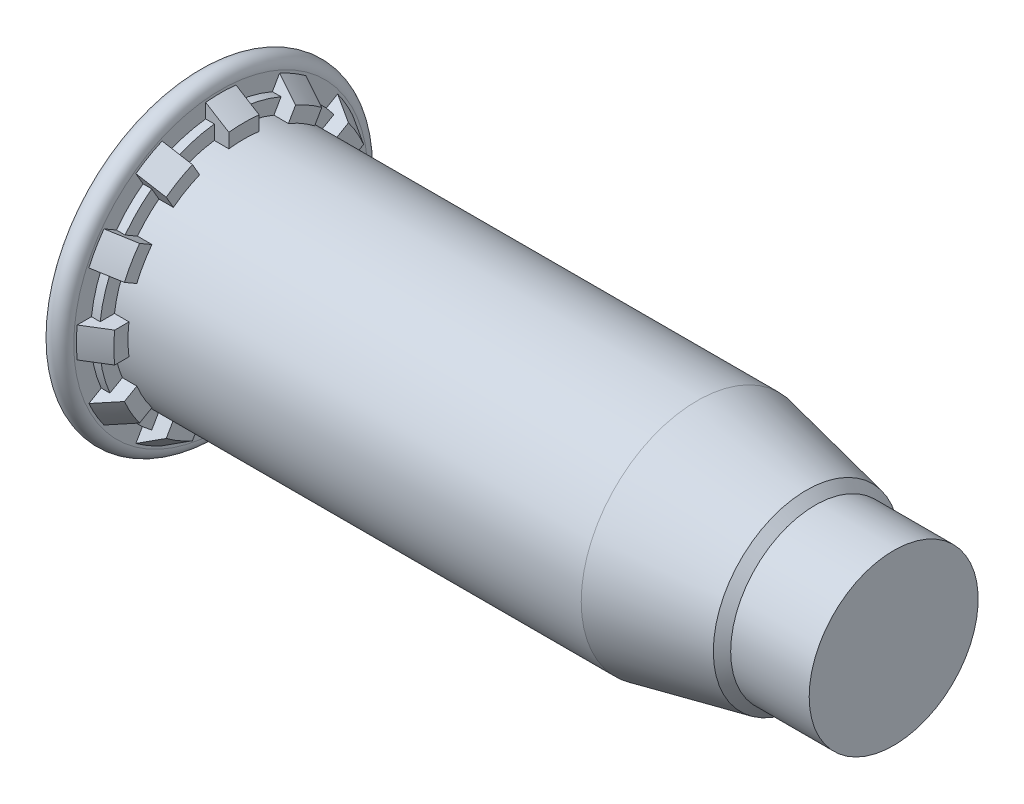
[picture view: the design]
ISO-10303-21;
HEADER;
FILE_DESCRIPTION(('STEP AP214'),'2;1');
FILE_NAME('part.step','',(''),(''),'','','');
FILE_SCHEMA(('AUTOMOTIVE_DESIGN { 1 0 10303 214 1 1 1 1 }'));
ENDSEC;
DATA;
#1=APPLICATION_CONTEXT('core data for automotive mechanical design processes');
#2=APPLICATION_PROTOCOL_DEFINITION('international standard','automotive_design',2000,#1);
#3=PRODUCT_CONTEXT('',#1,'mechanical');
#4=PRODUCT('Part','Part','',(#3));
#5=PRODUCT_RELATED_PRODUCT_CATEGORY('part','',(#4));
#6=PRODUCT_DEFINITION_FORMATION('','',#4);
#7=PRODUCT_DEFINITION_CONTEXT('part definition',#1,'design');
#8=PRODUCT_DEFINITION('design','',#6,#7);
#9=PRODUCT_DEFINITION_SHAPE('','',#8);
#10=(LENGTH_UNIT() NAMED_UNIT(*) SI_UNIT(.MILLI.,.METRE.));
#11=(NAMED_UNIT(*) PLANE_ANGLE_UNIT() SI_UNIT($,.RADIAN.));
#12=(NAMED_UNIT(*) SI_UNIT($,.STERADIAN.) SOLID_ANGLE_UNIT());
#13=UNCERTAINTY_MEASURE_WITH_UNIT(LENGTH_MEASURE(1.E-05),#10,'distance_accuracy_value','');
#14=(GEOMETRIC_REPRESENTATION_CONTEXT(3) GLOBAL_UNCERTAINTY_ASSIGNED_CONTEXT((#13)) GLOBAL_UNIT_ASSIGNED_CONTEXT((#10,
#11,#12)) REPRESENTATION_CONTEXT('',''));
#15=CARTESIAN_POINT('',(0.,0.,0.));
#16=DIRECTION('',(0.,0.,1.));
#17=DIRECTION('',(1.,0.,0.));
#18=AXIS2_PLACEMENT_3D('',#15,#16,#17);
#19=CARTESIAN_POINT('',(0.6,0.,0.));
#20=DIRECTION('',(-1.,0.,0.));
#21=DIRECTION('',(0.,0.,1.));
#22=AXIS2_PLACEMENT_3D('',#19,#20,#21);
#23=CONICAL_SURFACE('',#22,3.735,0.54956001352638);
#24=CARTESIAN_POINT('',(0.6,0.,0.));
#25=DIRECTION('',(-1.,0.,0.));
#26=DIRECTION('',(0.,0.,1.));
#27=AXIS2_PLACEMENT_3D('',#24,#25,#26);
#28=CIRCLE('',#27,3.735);
#29=CARTESIAN_POINT('',(0.6,3.02098991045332,2.19632533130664));
#30=VERTEX_POINT('',#29);
#31=CARTESIAN_POINT('',(0.6,3.41256848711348,1.51809134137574));
#32=VERTEX_POINT('',#31);
#33=EDGE_CURVE('E971',#30,#32,#28,.T.);
#34=ORIENTED_EDGE('',*,*,#33,.F.);
#35=CARTESIAN_POINT('',(1.2002,2.70066079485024,2.01138323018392));
#36=CARTESIAN_POINT('',(1.07508025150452,2.76747981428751,2.04996120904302));
#37=CARTESIAN_POINT('',(0.94994691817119,2.83427974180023,2.08852816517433));
#38=CARTESIAN_POINT('',(0.74980487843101,2.941079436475,2.15018899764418));
#39=CARTESIAN_POINT('',(0.67480487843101,2.98109143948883,2.17328993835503));
#40=CARTESIAN_POINT('',(0.5998,3.0210965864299,2.19638692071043));
#41=B_SPLINE_CURVE_WITH_KNOTS('',3,(#35,#36,#37,#38,#39,#40),.UNSPECIFIED.,.F.,.F.,(4,2,4),(0.,
0.44098970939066,0.705255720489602),.UNSPECIFIED.);
#42=CARTESIAN_POINT('',(1.2,2.70076760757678,2.01144489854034));
#43=VERTEX_POINT('',#42);
#44=EDGE_CURVE('E972',#43,#30,#41,.T.);
#45=ORIENTED_EDGE('',*,*,#44,.F.);
#46=CARTESIAN_POINT('',(1.2,0.,0.));
#47=DIRECTION('',(-1.,0.,0.));
#48=DIRECTION('',(0.,0.,1.));
#49=AXIS2_PLACEMENT_3D('',#46,#47,#48);
#50=CIRCLE('',#49,3.3675);
#51=CARTESIAN_POINT('',(1.2,3.09234618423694,1.33321090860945));
#52=VERTEX_POINT('',#51);
#53=EDGE_CURVE('E1239',#43,#52,#50,.T.);
#54=ORIENTED_EDGE('',*,*,#53,.T.);
#55=CARTESIAN_POINT('',(0.5998,3.41267516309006,1.51815293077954));
#56=CARTESIAN_POINT('',(0.67480487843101,3.37267001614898,1.49505594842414));
#57=CARTESIAN_POINT('',(0.74980487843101,3.33265801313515,1.47195500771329));
#58=CARTESIAN_POINT('',(0.94994691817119,3.22585831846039,1.41029417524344));
#59=CARTESIAN_POINT('',(1.07508025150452,3.15905839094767,1.37172721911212));
#60=CARTESIAN_POINT('',(1.2002,3.0922393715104,1.33314924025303));
#61=B_SPLINE_CURVE_WITH_KNOTS('',3,(#55,#56,#57,#58,#59,#60),.UNSPECIFIED.,.F.,.F.,(4,2,4),(0.,
0.264266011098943,0.705255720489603),.UNSPECIFIED.);
#62=EDGE_CURVE('E853',#32,#52,#61,.T.);
#63=ORIENTED_EDGE('',*,*,#62,.F.);
#64=EDGE_LOOP('',(#34,#45,#54,#63));
#65=FACE_BOUND('',#64,.T.);
#66=ADVANCED_FACE('F39',(#65),#23,.T.);
#67=CARTESIAN_POINT('',(0.5998,2.19638692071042,3.02109658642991));
#68=CARTESIAN_POINT('',(0.674804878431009,2.17328993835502,2.98109143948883));
#69=CARTESIAN_POINT('',(0.74980487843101,2.15018899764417,2.941079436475));
#70=CARTESIAN_POINT('',(0.94994691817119,2.08852816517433,2.83427974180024));
#71=CARTESIAN_POINT('',(1.07508025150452,2.04996120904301,2.76747981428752));
#72=CARTESIAN_POINT('',(1.2002,2.01138323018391,2.70066079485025));
#73=B_SPLINE_CURVE_WITH_KNOTS('',3,(#67,#68,#69,#70,#71,#72),.UNSPECIFIED.,.F.,.F.,(4,2,4),(0.,
0.264266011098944,0.705255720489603),.UNSPECIFIED.);
#74=CARTESIAN_POINT('',(0.6,2.19632533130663,3.02098991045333));
#75=VERTEX_POINT('',#74);
#76=CARTESIAN_POINT('',(1.2,2.01144489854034,2.70076760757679));
#77=VERTEX_POINT('',#76);
#78=EDGE_CURVE('E1281',#75,#77,#73,.T.);
#79=ORIENTED_EDGE('',*,*,#78,.F.);
#80=CARTESIAN_POINT('',(0.6,1.51809134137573,3.41256848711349));
#81=VERTEX_POINT('',#80);
#82=EDGE_CURVE('E501',#81,#75,#28,.T.);
#83=ORIENTED_EDGE('',*,*,#82,.F.);
#84=CARTESIAN_POINT('',(1.2002,1.33314924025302,3.0922393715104));
#85=CARTESIAN_POINT('',(1.07508025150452,1.37172721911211,3.15905839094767));
#86=CARTESIAN_POINT('',(0.94994691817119,1.41029417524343,3.22585831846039));
#87=CARTESIAN_POINT('',(0.749804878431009,1.47195500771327,3.33265801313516));
#88=CARTESIAN_POINT('',(0.674804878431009,1.49505594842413,3.37267001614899));
#89=CARTESIAN_POINT('',(0.5998,1.51815293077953,3.41267516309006));
#90=B_SPLINE_CURVE_WITH_KNOTS('',3,(#84,#85,#86,#87,#88,#89),.UNSPECIFIED.,.F.,.F.,(4,2,4),(0.,
0.440989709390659,0.705255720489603),.UNSPECIFIED.);
#91=CARTESIAN_POINT('',(1.2,1.33321090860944,3.09234618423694));
#92=VERTEX_POINT('',#91);
#93=EDGE_CURVE('E1021',#92,#81,#90,.T.);
#94=ORIENTED_EDGE('',*,*,#93,.F.);
#95=EDGE_CURVE('E1243',#92,#77,#50,.T.);
#96=ORIENTED_EDGE('',*,*,#95,.T.);
#97=EDGE_LOOP('',(#79,#83,#94,#96));
#98=FACE_BOUND('',#97,.T.);
#99=ADVANCED_FACE('F959',(#98),#23,.T.);
#100=CARTESIAN_POINT('',(-0.296527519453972,0.391578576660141,4.26618998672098));
#101=CARTESIAN_POINT('',(-0.286159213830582,0.391578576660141,4.25981269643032));
#102=CARTESIAN_POINT('',(-0.275790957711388,0.391578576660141,4.25343532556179));
#103=CARTESIAN_POINT('',(0.213231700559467,0.391578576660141,3.95263889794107));
#104=CARTESIAN_POINT('',(0.691778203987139,0.391578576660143,3.65804424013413));
#105=CARTESIAN_POINT('',(1.40926693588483,0.391578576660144,3.21561509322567));
#106=CARTESIAN_POINT('',(1.64837471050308,0.391578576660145,3.0680491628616));
#107=CARTESIAN_POINT('',(2.12640919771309,0.391578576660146,2.77262408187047));
#108=CARTESIAN_POINT('',(2.36533591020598,0.391578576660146,2.62476493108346));
#109=CARTESIAN_POINT('',(2.60413661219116,0.391578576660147,2.47670216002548));
#110=B_SPLINE_CURVE_WITH_KNOTS('',3,(#100,#101,#102,#103,#104,#105,#106,#107,#108,#109),
.UNSPECIFIED.,.F.,.F.,(4,2,2,2,4),(0.,0.0365177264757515,1.72238057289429,2.56531223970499,
3.40824436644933),.UNSPECIFIED.);
#111=CARTESIAN_POINT('',(0.6,0.391578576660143,3.71441667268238));
#112=VERTEX_POINT('',#111);
#113=CARTESIAN_POINT('',(1.2,0.391578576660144,3.34465580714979));
#114=VERTEX_POINT('',#113);
#115=EDGE_CURVE('E1020',#112,#114,#110,.T.);
#116=ORIENTED_EDGE('',*,*,#115,.F.);
#117=CARTESIAN_POINT('',(0.6,-0.391578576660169,3.71441667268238));
#118=VERTEX_POINT('',#117);
#119=EDGE_CURVE('E977',#118,#112,#28,.T.);
#120=ORIENTED_EDGE('',*,*,#119,.F.);
#121=CARTESIAN_POINT('',(2.60413661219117,-0.391578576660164,2.47670216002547));
#122=CARTESIAN_POINT('',(2.36533591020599,-0.391578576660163,2.62476493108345));
#123=CARTESIAN_POINT('',(2.12640919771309,-0.391578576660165,2.77262408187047));
#124=CARTESIAN_POINT('',(1.64837471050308,-0.391578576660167,3.0680491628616));
#125=CARTESIAN_POINT('',(1.40926693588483,-0.391578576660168,3.21561509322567));
#126=CARTESIAN_POINT('',(0.691778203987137,-0.391578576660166,3.65804424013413));
#127=CARTESIAN_POINT('',(0.213231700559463,-0.391578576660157,3.95263889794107));
#128=CARTESIAN_POINT('',(-0.275790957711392,-0.391578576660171,4.25343532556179));
#129=CARTESIAN_POINT('',(-0.286159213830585,-0.391578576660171,4.25981269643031));
#130=CARTESIAN_POINT('',(-0.296527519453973,-0.391578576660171,4.26618998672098));
#131=B_SPLINE_CURVE_WITH_KNOTS('',3,(#121,#122,#123,#124,#125,#126,#127,#128,#129,#130),
.UNSPECIFIED.,.F.,.F.,(4,2,2,2,4),(0.,0.842932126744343,1.68586379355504,3.37172663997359,
3.40824436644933),.UNSPECIFIED.);
#132=CARTESIAN_POINT('',(1.2,-0.391578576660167,3.34465580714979));
#133=VERTEX_POINT('',#132);
#134=EDGE_CURVE('E1012',#133,#118,#131,.T.);
#135=ORIENTED_EDGE('',*,*,#134,.F.);
#136=EDGE_CURVE('E1018',#133,#114,#50,.T.);
#137=ORIENTED_EDGE('',*,*,#136,.T.);
#138=EDGE_LOOP('',(#116,#120,#135,#137));
#139=FACE_BOUND('',#138,.T.);
#140=ADVANCED_FACE('F967',(#139),#23,.T.);
#141=CARTESIAN_POINT('',(0.5998,-1.51815293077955,3.41267516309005));
#142=CARTESIAN_POINT('',(0.67480487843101,-1.49505594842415,3.37267001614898));
#143=CARTESIAN_POINT('',(0.74980487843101,-1.4719550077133,3.33265801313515));
#144=CARTESIAN_POINT('',(0.94994691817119,-1.41029417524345,3.22585831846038));
#145=CARTESIAN_POINT('',(1.07508025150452,-1.37172721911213,3.15905839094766));
#146=CARTESIAN_POINT('',(1.2002,-1.33314924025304,3.09223937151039));
#147=B_SPLINE_CURVE_WITH_KNOTS('',3,(#141,#142,#143,#144,#145,#146),.UNSPECIFIED.,.F.,.F.,(4,2,
4),(0.,0.264266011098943,0.705255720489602),.UNSPECIFIED.);
#148=CARTESIAN_POINT('',(0.6,-1.51809134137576,3.41256848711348));
#149=VERTEX_POINT('',#148);
#150=CARTESIAN_POINT('',(1.2,-1.33321090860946,3.09234618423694));
#151=VERTEX_POINT('',#150);
#152=EDGE_CURVE('E1037',#149,#151,#147,.T.);
#153=ORIENTED_EDGE('',*,*,#152,.F.);
#154=CARTESIAN_POINT('',(0.6,-2.19632533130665,3.02098991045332));
#155=VERTEX_POINT('',#154);
#156=EDGE_CURVE('E1004',#155,#149,#28,.T.);
#157=ORIENTED_EDGE('',*,*,#156,.F.);
#158=CARTESIAN_POINT('',(1.2002,-2.01138323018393,2.70066079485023));
#159=CARTESIAN_POINT('',(1.07508025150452,-2.04996120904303,2.7674798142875));
#160=CARTESIAN_POINT('',(0.949946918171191,-2.08852816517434,2.83427974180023));
#161=CARTESIAN_POINT('',(0.74980487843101,-2.15018899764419,2.94107943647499));
#162=CARTESIAN_POINT('',(0.67480487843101,-2.17328993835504,2.98109143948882));
#163=CARTESIAN_POINT('',(0.5998,-2.19638692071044,3.02109658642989));
#164=B_SPLINE_CURVE_WITH_KNOTS('',3,(#158,#159,#160,#161,#162,#163),.UNSPECIFIED.,.F.,.F.,(4,2,
4),(0.,0.44098970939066,0.705255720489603),.UNSPECIFIED.);
#165=CARTESIAN_POINT('',(1.2,-2.01144489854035,2.70076760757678));
#166=VERTEX_POINT('',#165);
#167=EDGE_CURVE('E1087',#166,#155,#164,.T.);
#168=ORIENTED_EDGE('',*,*,#167,.F.);
#169=EDGE_CURVE('E1352',#166,#151,#50,.T.);
#170=ORIENTED_EDGE('',*,*,#169,.T.);
#171=EDGE_LOOP('',(#153,#157,#168,#170));
#172=FACE_BOUND('',#171,.T.);
#173=ADVANCED_FACE('F1489',(#172),#23,.T.);
#174=CARTESIAN_POINT('',(0.5998,-3.02109658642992,2.19638692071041));
#175=CARTESIAN_POINT('',(0.67480487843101,-2.98109143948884,2.17328993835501));
#176=CARTESIAN_POINT('',(0.74980487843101,-2.94107943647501,2.15018899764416));
#177=CARTESIAN_POINT('',(0.94994691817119,-2.83427974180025,2.08852816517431));
#178=CARTESIAN_POINT('',(1.07508025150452,-2.76747981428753,2.049961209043));
#179=CARTESIAN_POINT('',(1.2002,-2.70066079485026,2.0113832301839));
#180=B_SPLINE_CURVE_WITH_KNOTS('',3,(#174,#175,#176,#177,#178,#179),.UNSPECIFIED.,.F.,.F.,(4,2,
4),(0.,0.264266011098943,0.705255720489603),.UNSPECIFIED.);
#181=CARTESIAN_POINT('',(0.6,-3.02098991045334,2.19632533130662));
#182=VERTEX_POINT('',#181);
#183=CARTESIAN_POINT('',(1.2,-2.7007676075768,2.01144489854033));
#184=VERTEX_POINT('',#183);
#185=EDGE_CURVE('E1083',#182,#184,#180,.T.);
#186=ORIENTED_EDGE('',*,*,#185,.F.);
#187=CARTESIAN_POINT('',(0.6,-3.41256848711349,1.51809134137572));
#188=VERTEX_POINT('',#187);
#189=EDGE_CURVE('E999',#188,#182,#28,.T.);
#190=ORIENTED_EDGE('',*,*,#189,.F.);
#191=CARTESIAN_POINT('',(1.2002,-3.09223937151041,1.33314924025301));
#192=CARTESIAN_POINT('',(1.07508025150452,-3.15905839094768,1.3717272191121));
#193=CARTESIAN_POINT('',(0.949946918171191,-3.2258583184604,1.41029417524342));
#194=CARTESIAN_POINT('',(0.74980487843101,-3.33265801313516,1.47195500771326));
#195=CARTESIAN_POINT('',(0.67480487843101,-3.37267001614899,1.49505594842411));
#196=CARTESIAN_POINT('',(0.5998,-3.41267516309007,1.51815293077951));
#197=B_SPLINE_CURVE_WITH_KNOTS('',3,(#191,#192,#193,#194,#195,#196),.UNSPECIFIED.,.F.,.F.,(4,2,
4),(0.,0.44098970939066,0.705255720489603),.UNSPECIFIED.);
#198=CARTESIAN_POINT('',(1.2,-3.09234618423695,1.33321090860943));
#199=VERTEX_POINT('',#198);
#200=EDGE_CURVE('E1123',#199,#188,#197,.T.);
#201=ORIENTED_EDGE('',*,*,#200,.F.);
#202=EDGE_CURVE('E1348',#199,#184,#50,.T.);
#203=ORIENTED_EDGE('',*,*,#202,.T.);
#204=EDGE_LOOP('',(#186,#190,#201,#203));
#205=FACE_BOUND('',#204,.T.);
#206=ADVANCED_FACE('F1456',(#205),#23,.T.);
#207=CARTESIAN_POINT('',(-0.571392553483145,-4.43522558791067,0.391578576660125));
#208=CARTESIAN_POINT('',(-0.33204367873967,-4.28805118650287,0.391578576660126));
#209=CARTESIAN_POINT('',(-0.092717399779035,-4.1408400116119,0.391578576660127));
#210=CARTESIAN_POINT('',(0.385864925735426,-3.84630382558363,0.391578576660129));
#211=CARTESIAN_POINT('',(0.62512097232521,-3.69897881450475,0.39157857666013));
#212=CARTESIAN_POINT('',(1.10353812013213,-3.404174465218,0.391578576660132));
#213=CARTESIAN_POINT('',(1.34269922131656,-3.25669512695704,0.391578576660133));
#214=CARTESIAN_POINT('',(1.82087179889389,-2.96149383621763,0.391578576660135));
#215=CARTESIAN_POINT('',(2.05988327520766,-2.81377188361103,0.391578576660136));
#216=CARTESIAN_POINT('',(2.29879251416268,-2.66588453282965,0.391578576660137));
#217=B_SPLINE_CURVE_WITH_KNOTS('',3,(#207,#208,#209,#210,#211,#212,#213,#214,#215,#216),
.UNSPECIFIED.,.F.,.F.,(4,2,2,2,4),(0.,0.84293162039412,1.68586280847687,2.52879428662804,
3.3717262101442),.UNSPECIFIED.);
#218=CARTESIAN_POINT('',(0.6,-3.71441667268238,0.39157857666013));
#219=VERTEX_POINT('',#218);
#220=CARTESIAN_POINT('',(1.2,-3.34465580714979,0.391578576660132));
#221=VERTEX_POINT('',#220);
#222=EDGE_CURVE('E1116',#219,#221,#217,.T.);
#223=ORIENTED_EDGE('',*,*,#222,.F.);
#224=CARTESIAN_POINT('',(0.6,-3.71441667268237,-0.391578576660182));
#225=VERTEX_POINT('',#224);
#226=EDGE_CURVE('E1000',#225,#219,#28,.T.);
#227=ORIENTED_EDGE('',*,*,#226,.F.);
#228=CARTESIAN_POINT('',(2.29879251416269,-2.66588453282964,-0.391578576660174));
#229=CARTESIAN_POINT('',(2.05988327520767,-2.81377188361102,-0.391578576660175));
#230=CARTESIAN_POINT('',(1.8208717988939,-2.96149383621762,-0.391578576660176));
#231=CARTESIAN_POINT('',(1.34269922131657,-3.25669512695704,-0.391578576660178));
#232=CARTESIAN_POINT('',(1.10353812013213,-3.404174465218,-0.391578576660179));
#233=CARTESIAN_POINT('',(0.625120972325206,-3.69897881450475,-0.391578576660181));
#234=CARTESIAN_POINT('',(0.385864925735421,-3.84630382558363,-0.391578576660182));
#235=CARTESIAN_POINT('',(-0.0927173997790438,-4.1408400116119,-0.391578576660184));
#236=CARTESIAN_POINT('',(-0.33204367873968,-4.28805118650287,-0.391578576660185));
#237=CARTESIAN_POINT('',(-0.571392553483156,-4.43522558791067,-0.391578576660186));
#238=B_SPLINE_CURVE_WITH_KNOTS('',3,(#228,#229,#230,#231,#232,#233,#234,#235,#236,#237),
.UNSPECIFIED.,.F.,.F.,(4,2,2,2,4),(0.,0.842931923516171,1.68586340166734,2.5287945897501,
3.37172621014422),.UNSPECIFIED.);
#239=CARTESIAN_POINT('',(1.2,-3.34465580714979,-0.391578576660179));
#240=VERTEX_POINT('',#239);
#241=EDGE_CURVE('E1137',#240,#225,#238,.T.);
#242=ORIENTED_EDGE('',*,*,#241,.F.);
#243=EDGE_CURVE('E1343',#240,#221,#50,.T.);
#244=ORIENTED_EDGE('',*,*,#243,.T.);
#245=EDGE_LOOP('',(#223,#227,#242,#244));
#246=FACE_BOUND('',#245,.T.);
#247=ADVANCED_FACE('F1454',(#246),#23,.T.);
#248=CARTESIAN_POINT('',(0.5998,-3.41267516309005,-1.51815293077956));
#249=CARTESIAN_POINT('',(0.674804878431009,-3.37267001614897,-1.49505594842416));
#250=CARTESIAN_POINT('',(0.74980487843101,-3.33265801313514,-1.47195500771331));
#251=CARTESIAN_POINT('',(0.94994691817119,-3.22585831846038,-1.41029417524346));
#252=CARTESIAN_POINT('',(1.07508025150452,-3.15905839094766,-1.37172721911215));
#253=CARTESIAN_POINT('',(1.2002,-3.09223937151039,-1.33314924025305));
#254=B_SPLINE_CURVE_WITH_KNOTS('',3,(#248,#249,#250,#251,#252,#253),.UNSPECIFIED.,.F.,.F.,(4,2,
4),(0.,0.264266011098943,0.705255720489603),.UNSPECIFIED.);
#255=CARTESIAN_POINT('',(0.6,-3.41256848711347,-1.51809134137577));
#256=VERTEX_POINT('',#255);
#257=CARTESIAN_POINT('',(1.2,-3.09234618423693,-1.33321090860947));
#258=VERTEX_POINT('',#257);
#259=EDGE_CURVE('E1129',#256,#258,#254,.T.);
#260=ORIENTED_EDGE('',*,*,#259,.F.);
#261=CARTESIAN_POINT('',(0.6,-3.02098991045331,-2.19632533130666));
#262=VERTEX_POINT('',#261);
#263=EDGE_CURVE('E993',#262,#256,#28,.T.);
#264=ORIENTED_EDGE('',*,*,#263,.F.);
#265=CARTESIAN_POINT('',(1.2002,-2.70066079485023,-2.01138323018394));
#266=CARTESIAN_POINT('',(1.07508025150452,-2.7674798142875,-2.04996120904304));
#267=CARTESIAN_POINT('',(0.949946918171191,-2.83427974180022,-2.08852816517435));
#268=CARTESIAN_POINT('',(0.74980487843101,-2.94107943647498,-2.1501889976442));
#269=CARTESIAN_POINT('',(0.67480487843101,-2.98109143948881,-2.17328993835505));
#270=CARTESIAN_POINT('',(0.5998,-3.02109658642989,-2.19638692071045));
#271=B_SPLINE_CURVE_WITH_KNOTS('',3,(#265,#266,#267,#268,#269,#270),.UNSPECIFIED.,.F.,.F.,(4,2,
4),(0.,0.44098970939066,0.705255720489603),.UNSPECIFIED.);
#272=CARTESIAN_POINT('',(1.2,-2.70076760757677,-2.01144489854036));
#273=VERTEX_POINT('',#272);
#274=EDGE_CURVE('E1175',#273,#262,#271,.T.);
#275=ORIENTED_EDGE('',*,*,#274,.F.);
#276=EDGE_CURVE('E1336',#273,#258,#50,.T.);
#277=ORIENTED_EDGE('',*,*,#276,.T.);
#278=EDGE_LOOP('',(#260,#264,#275,#277));
#279=FACE_BOUND('',#278,.T.);
#280=ADVANCED_FACE('F1451',(#279),#23,.T.);
#281=CARTESIAN_POINT('',(0.5998,-2.1963869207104,-3.02109658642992));
#282=CARTESIAN_POINT('',(0.674804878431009,-2.173289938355,-2.98109143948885));
#283=CARTESIAN_POINT('',(0.74980487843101,-2.15018899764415,-2.94107943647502));
#284=CARTESIAN_POINT('',(0.94994691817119,-2.08852816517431,-2.83427974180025));
#285=CARTESIAN_POINT('',(1.07508025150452,-2.04996120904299,-2.76747981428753));
#286=CARTESIAN_POINT('',(1.2002,-2.01138323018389,-2.70066079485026));
#287=B_SPLINE_CURVE_WITH_KNOTS('',3,(#281,#282,#283,#284,#285,#286),.UNSPECIFIED.,.F.,.F.,(4,2,
4),(0.,0.264266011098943,0.705255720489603),.UNSPECIFIED.);
#288=CARTESIAN_POINT('',(0.6,-2.19632533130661,-3.02098991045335));
#289=VERTEX_POINT('',#288);
#290=CARTESIAN_POINT('',(1.2,-2.01144489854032,-2.7007676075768));
#291=VERTEX_POINT('',#290);
#292=EDGE_CURVE('E1166',#289,#291,#287,.T.);
#293=ORIENTED_EDGE('',*,*,#292,.F.);
#294=CARTESIAN_POINT('',(0.6,-1.51809134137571,-3.4125684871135));
#295=VERTEX_POINT('',#294);
#296=EDGE_CURVE('E991',#295,#289,#28,.T.);
#297=ORIENTED_EDGE('',*,*,#296,.F.);
#298=CARTESIAN_POINT('',(1.2002,-1.333149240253,-3.09223937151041));
#299=CARTESIAN_POINT('',(1.07508025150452,-1.37172721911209,-3.15905839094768));
#300=CARTESIAN_POINT('',(0.949946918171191,-1.41029417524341,-3.2258583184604));
#301=CARTESIAN_POINT('',(0.74980487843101,-1.47195500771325,-3.33265801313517));
#302=CARTESIAN_POINT('',(0.67480487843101,-1.4950559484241,-3.372670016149));
#303=CARTESIAN_POINT('',(0.5998,-1.5181529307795,-3.41267516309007));
#304=B_SPLINE_CURVE_WITH_KNOTS('',3,(#298,#299,#300,#301,#302,#303),.UNSPECIFIED.,.F.,.F.,(4,2,
4),(0.,0.44098970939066,0.705255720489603),.UNSPECIFIED.);
#305=CARTESIAN_POINT('',(1.2,-1.33321090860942,-3.09234618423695));
#306=VERTEX_POINT('',#305);
#307=EDGE_CURVE('E1183',#306,#295,#304,.T.);
#308=ORIENTED_EDGE('',*,*,#307,.F.);
#309=EDGE_CURVE('E1338',#306,#291,#50,.T.);
#310=ORIENTED_EDGE('',*,*,#309,.T.);
#311=EDGE_LOOP('',(#293,#297,#308,#310));
#312=FACE_BOUND('',#311,.T.);
#313=ADVANCED_FACE('F1435',(#312),#23,.T.);
#314=CARTESIAN_POINT('',(-0.571392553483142,-0.391578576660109,-4.43522558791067));
#315=CARTESIAN_POINT('',(-0.332043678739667,-0.391578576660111,-4.28805118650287));
#316=CARTESIAN_POINT('',(-0.0927173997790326,-0.391578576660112,-4.1408400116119));
#317=CARTESIAN_POINT('',(0.385864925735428,-0.391578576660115,-3.84630382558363));
#318=CARTESIAN_POINT('',(0.625120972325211,-0.391578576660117,-3.69897881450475));
#319=CARTESIAN_POINT('',(1.10353812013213,-0.39157857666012,-3.404174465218));
#320=CARTESIAN_POINT('',(1.34269922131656,-0.391578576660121,-3.25669512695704));
#321=CARTESIAN_POINT('',(1.82087179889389,-0.391578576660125,-2.96149383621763));
#322=CARTESIAN_POINT('',(2.05988327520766,-0.391578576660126,-2.81377188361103));
#323=CARTESIAN_POINT('',(2.29879251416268,-0.391578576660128,-2.66588453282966));
#324=B_SPLINE_CURVE_WITH_KNOTS('',3,(#314,#315,#316,#317,#318,#319,#320,#321,#322,#323),
.UNSPECIFIED.,.F.,.F.,(4,2,2,2,4),(0.,0.842931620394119,1.68586280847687,2.52879428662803,
3.3717262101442),.UNSPECIFIED.);
#325=CARTESIAN_POINT('',(0.6,-0.391578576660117,-3.71441667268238));
#326=VERTEX_POINT('',#325);
#327=CARTESIAN_POINT('',(1.2,-0.391578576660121,-3.34465580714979));
#328=VERTEX_POINT('',#327);
#329=EDGE_CURVE('E1179',#326,#328,#324,.T.);
#330=ORIENTED_EDGE('',*,*,#329,.F.);
#331=CARTESIAN_POINT('',(0.6,0.391578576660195,-3.71441667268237));
#332=VERTEX_POINT('',#331);
#333=EDGE_CURVE('E986',#332,#326,#28,.T.);
#334=ORIENTED_EDGE('',*,*,#333,.F.);
#335=CARTESIAN_POINT('',(2.29879251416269,0.391578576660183,-2.66588453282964));
#336=CARTESIAN_POINT('',(2.05988327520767,0.391578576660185,-2.81377188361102));
#337=CARTESIAN_POINT('',(1.8208717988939,0.391578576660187,-2.96149383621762));
#338=CARTESIAN_POINT('',(1.34269922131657,0.39157857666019,-3.25669512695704));
#339=CARTESIAN_POINT('',(1.10353812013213,0.391578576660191,-3.404174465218));
#340=CARTESIAN_POINT('',(0.625120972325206,0.391578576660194,-3.69897881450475));
#341=CARTESIAN_POINT('',(0.38586492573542,0.391578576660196,-3.84630382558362));
#342=CARTESIAN_POINT('',(-0.0927173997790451,0.391578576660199,-4.1408400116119));
#343=CARTESIAN_POINT('',(-0.332043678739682,0.3915785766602,-4.28805118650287));
#344=CARTESIAN_POINT('',(-0.571392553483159,0.391578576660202,-4.43522558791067));
#345=B_SPLINE_CURVE_WITH_KNOTS('',3,(#335,#336,#337,#338,#339,#340,#341,#342,#343,#344),
.UNSPECIFIED.,.F.,.F.,(4,2,2,2,4),(0.,0.842931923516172,1.68586340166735,2.5287945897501,
3.37172621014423),.UNSPECIFIED.);
#346=CARTESIAN_POINT('',(1.2,0.391578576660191,-3.34465580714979));
#347=VERTEX_POINT('',#346);
#348=EDGE_CURVE('E1220',#347,#332,#345,.T.);
#349=ORIENTED_EDGE('',*,*,#348,.F.);
#350=EDGE_CURVE('E1244',#347,#328,#50,.T.);
#351=ORIENTED_EDGE('',*,*,#350,.T.);
#352=EDGE_LOOP('',(#330,#334,#349,#351));
#353=FACE_BOUND('',#352,.T.);
#354=ADVANCED_FACE('F1441',(#353),#23,.T.);
#355=CARTESIAN_POINT('',(0.5998,1.51815293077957,-3.41267516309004));
#356=CARTESIAN_POINT('',(0.67480487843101,1.49505594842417,-3.37267001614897));
#357=CARTESIAN_POINT('',(0.74980487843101,1.47195500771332,-3.33265801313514));
#358=CARTESIAN_POINT('',(0.94994691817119,1.41029417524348,-3.22585831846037));
#359=CARTESIAN_POINT('',(1.07508025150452,1.37172721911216,-3.15905839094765));
#360=CARTESIAN_POINT('',(1.2002,1.33314924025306,-3.09223937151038));
#361=B_SPLINE_CURVE_WITH_KNOTS('',3,(#355,#356,#357,#358,#359,#360),.UNSPECIFIED.,.F.,.F.,(4,2,
4),(0.,0.264266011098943,0.705255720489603),.UNSPECIFIED.);
#362=CARTESIAN_POINT('',(0.6,1.51809134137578,-3.41256848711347));
#363=VERTEX_POINT('',#362);
#364=CARTESIAN_POINT('',(1.2,1.33321090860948,-3.09234618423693));
#365=VERTEX_POINT('',#364);
#366=EDGE_CURVE('E1215',#363,#365,#361,.T.);
#367=ORIENTED_EDGE('',*,*,#366,.F.);
#368=CARTESIAN_POINT('',(0.6,2.19632533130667,-3.0209899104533));
#369=VERTEX_POINT('',#368);
#370=EDGE_CURVE('E979',#369,#363,#28,.T.);
#371=ORIENTED_EDGE('',*,*,#370,.F.);
#372=CARTESIAN_POINT('',(1.2002,2.01138323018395,-2.70066079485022));
#373=CARTESIAN_POINT('',(1.07508025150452,2.04996120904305,-2.76747981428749));
#374=CARTESIAN_POINT('',(0.94994691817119,2.08852816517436,-2.83427974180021));
#375=CARTESIAN_POINT('',(0.74980487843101,2.15018899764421,-2.94107943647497));
#376=CARTESIAN_POINT('',(0.67480487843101,2.17328993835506,-2.9810914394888));
#377=CARTESIAN_POINT('',(0.5998,2.19638692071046,-3.02109658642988));
#378=B_SPLINE_CURVE_WITH_KNOTS('',3,(#372,#373,#374,#375,#376,#377),.UNSPECIFIED.,.F.,.F.,(4,2,
4),(0.,0.440989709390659,0.705255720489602),.UNSPECIFIED.);
#379=CARTESIAN_POINT('',(1.2,2.01144489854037,-2.70076760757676));
#380=VERTEX_POINT('',#379);
#381=EDGE_CURVE('E665',#380,#369,#378,.T.);
#382=ORIENTED_EDGE('',*,*,#381,.F.);
#383=EDGE_CURVE('E1238',#380,#365,#50,.T.);
#384=ORIENTED_EDGE('',*,*,#383,.T.);
#385=EDGE_LOOP('',(#367,#371,#382,#384));
#386=FACE_BOUND('',#385,.T.);
#387=ADVANCED_FACE('F1443',(#386),#23,.T.);
#388=CARTESIAN_POINT('',(0.6,3.71441667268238,0.391578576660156));
#389=VERTEX_POINT('',#388);
#390=CARTESIAN_POINT('',(0.6,3.71441667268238,-0.391578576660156));
#391=VERTEX_POINT('',#390);
#392=EDGE_CURVE('E975',#389,#391,#28,.T.);
#393=ORIENTED_EDGE('',*,*,#392,.F.);
#394=CARTESIAN_POINT('',(2.60413661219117,2.47670216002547,0.391578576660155));
#395=CARTESIAN_POINT('',(2.36533591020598,2.62476493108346,0.391578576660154));
#396=CARTESIAN_POINT('',(2.12640919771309,2.77262408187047,0.391578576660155));
#397=CARTESIAN_POINT('',(1.64837471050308,3.0680491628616,0.391578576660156));
#398=CARTESIAN_POINT('',(1.40926693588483,3.21561509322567,0.391578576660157));
#399=CARTESIAN_POINT('',(0.691778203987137,3.65804424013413,0.391578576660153));
#400=CARTESIAN_POINT('',(0.213231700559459,3.95263889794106,0.391578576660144));
#401=CARTESIAN_POINT('',(-0.275790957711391,4.25343532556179,0.391578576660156));
#402=CARTESIAN_POINT('',(-0.286159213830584,4.25981269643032,0.391578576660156));
#403=CARTESIAN_POINT('',(-0.296527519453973,4.26618998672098,0.391578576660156));
#404=B_SPLINE_CURVE_WITH_KNOTS('',3,(#394,#395,#396,#397,#398,#399,#400,#401,#402,#403),
.UNSPECIFIED.,.F.,.F.,(4,2,2,2,4),(0.,0.842932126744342,1.68586379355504,3.37172663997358,
3.40824436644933),.UNSPECIFIED.);
#405=CARTESIAN_POINT('',(1.2,3.34465580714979,0.391578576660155));
#406=VERTEX_POINT('',#405);
#407=EDGE_CURVE('E863',#406,#389,#404,.T.);
#408=ORIENTED_EDGE('',*,*,#407,.F.);
#409=CARTESIAN_POINT('',(1.2,3.34465580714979,-0.391578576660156));
#410=VERTEX_POINT('',#409);
#411=EDGE_CURVE('E1242',#406,#410,#50,.T.);
#412=ORIENTED_EDGE('',*,*,#411,.T.);
#413=CARTESIAN_POINT('',(-0.296527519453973,4.26618998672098,-0.391578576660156));
#414=CARTESIAN_POINT('',(-0.286159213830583,4.25981269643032,-0.391578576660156));
#415=CARTESIAN_POINT('',(-0.27579095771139,4.25343532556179,-0.391578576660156));
#416=CARTESIAN_POINT('',(0.213231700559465,3.95263889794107,-0.391578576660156));
#417=CARTESIAN_POINT('',(0.691778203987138,3.65804424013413,-0.391578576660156));
#418=CARTESIAN_POINT('',(1.40926693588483,3.21561509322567,-0.391578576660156));
#419=CARTESIAN_POINT('',(1.64837471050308,3.0680491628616,-0.391578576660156));
#420=CARTESIAN_POINT('',(2.12640919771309,2.77262408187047,-0.391578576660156));
#421=CARTESIAN_POINT('',(2.36533591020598,2.62476493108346,-0.391578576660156));
#422=CARTESIAN_POINT('',(2.60413661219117,2.47670216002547,-0.391578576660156));
#423=B_SPLINE_CURVE_WITH_KNOTS('',3,(#413,#414,#415,#416,#417,#418,#419,#420,#421,#422),
.UNSPECIFIED.,.F.,.F.,(4,2,2,2,4),(0.,0.0365177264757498,1.72238057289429,2.56531223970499,
3.40824436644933),.UNSPECIFIED.);
#424=EDGE_CURVE('E907',#391,#410,#423,.T.);
#425=ORIENTED_EDGE('',*,*,#424,.F.);
#426=EDGE_LOOP('',(#393,#408,#412,#425));
#427=FACE_BOUND('',#426,.T.);
#428=ADVANCED_FACE('F951',(#427),#23,.T.);
#429=CARTESIAN_POINT('',(1.2,3.3675,0.));
#430=DIRECTION('',(1.,0.,0.));
#431=DIRECTION('',(0.,0.,-1.));
#432=AXIS2_PLACEMENT_3D('',#429,#430,#431);
#433=PLANE('',#432);
#434=DIRECTION('',(0.,-0.499999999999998,-0.86602540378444));
#435=VECTOR('',#434,1.);
#436=CARTESIAN_POINT('',(1.2,1.82628428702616,2.38006002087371));
#437=LINE('',#436,#435);
#438=CARTESIAN_POINT('',(1.2,1.82628428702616,2.38006002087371));
#439=VERTEX_POINT('',#438);
#440=EDGE_CURVE('E652',#77,#439,#437,.T.);
#441=ORIENTED_EDGE('',*,*,#440,.F.);
#442=ORIENTED_EDGE('',*,*,#95,.F.);
#443=DIRECTION('',(0.,0.499999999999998,0.86602540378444));
#444=VECTOR('',#443,1.);
#445=CARTESIAN_POINT('',(1.2,1.14805029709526,2.77163859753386));
#446=LINE('',#445,#444);
#447=CARTESIAN_POINT('',(1.2,1.14805029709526,2.77163859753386));
#448=VERTEX_POINT('',#447);
#449=EDGE_CURVE('E673',#448,#92,#446,.T.);
#450=ORIENTED_EDGE('',*,*,#449,.F.);
#451=CARTESIAN_POINT('',(1.2,0.,0.));
#452=DIRECTION('',(-1.,0.,0.));
#453=DIRECTION('',(0.,0.,1.));
#454=AXIS2_PLACEMENT_3D('',#451,#452,#453);
#455=CIRCLE('',#454,3.);
#456=EDGE_CURVE('E1260',#448,#439,#455,.T.);
#457=ORIENTED_EDGE('',*,*,#456,.T.);
#458=EDGE_LOOP('',(#441,#442,#450,#457));
#459=FACE_BOUND('',#458,.T.);
#460=ADVANCED_FACE('F944',(#459),#433,.T.);
#461=DIRECTION('',(0.,0.,-1.));
#462=VECTOR('',#461,1.);
#463=CARTESIAN_POINT('',(1.2,0.391578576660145,2.97433458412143));
#464=LINE('',#463,#462);
#465=CARTESIAN_POINT('',(1.2,0.391578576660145,2.97433458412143));
#466=VERTEX_POINT('',#465);
#467=EDGE_CURVE('E669',#114,#466,#464,.T.);
#468=ORIENTED_EDGE('',*,*,#467,.F.);
#469=ORIENTED_EDGE('',*,*,#136,.F.);
#470=DIRECTION('',(0.,0.,1.));
#471=VECTOR('',#470,1.);
#472=CARTESIAN_POINT('',(1.2,-0.391578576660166,2.97433458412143));
#473=LINE('',#472,#471);
#474=CARTESIAN_POINT('',(1.2,-0.391578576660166,2.97433458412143));
#475=VERTEX_POINT('',#474);
#476=EDGE_CURVE('E687',#475,#133,#473,.T.);
#477=ORIENTED_EDGE('',*,*,#476,.F.);
#478=EDGE_CURVE('E1389',#475,#466,#455,.T.);
#479=ORIENTED_EDGE('',*,*,#478,.T.);
#480=EDGE_LOOP('',(#468,#469,#477,#479));
#481=FACE_BOUND('',#480,.T.);
#482=ADVANCED_FACE('F952',(#481),#433,.T.);
#483=DIRECTION('',(0.,0.500000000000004,-0.866025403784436));
#484=VECTOR('',#483,1.);
#485=CARTESIAN_POINT('',(1.2,-1.14805029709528,2.77163859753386));
#486=LINE('',#485,#484);
#487=CARTESIAN_POINT('',(1.2,-1.14805029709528,2.77163859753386));
#488=VERTEX_POINT('',#487);
#489=EDGE_CURVE('E685',#151,#488,#486,.T.);
#490=ORIENTED_EDGE('',*,*,#489,.F.);
#491=ORIENTED_EDGE('',*,*,#169,.F.);
#492=DIRECTION('',(0.,-0.500000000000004,0.866025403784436));
#493=VECTOR('',#492,1.);
#494=CARTESIAN_POINT('',(1.2,-1.82628428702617,2.3800600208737));
#495=LINE('',#494,#493);
#496=CARTESIAN_POINT('',(1.2,-1.82628428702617,2.3800600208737));
#497=VERTEX_POINT('',#496);
#498=EDGE_CURVE('E710',#497,#166,#495,.T.);
#499=ORIENTED_EDGE('',*,*,#498,.F.);
#500=EDGE_CURVE('E1395',#497,#488,#455,.T.);
#501=ORIENTED_EDGE('',*,*,#500,.T.);
#502=EDGE_LOOP('',(#490,#491,#499,#501));
#503=FACE_BOUND('',#502,.T.);
#504=ADVANCED_FACE('F1486',(#503),#433,.T.);
#505=DIRECTION('',(0.,0.866025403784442,-0.499999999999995));
#506=VECTOR('',#505,1.);
#507=CARTESIAN_POINT('',(1.2,-2.38006002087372,1.82628428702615));
#508=LINE('',#507,#506);
#509=CARTESIAN_POINT('',(1.2,-2.38006002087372,1.82628428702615));
#510=VERTEX_POINT('',#509);
#511=EDGE_CURVE('E701',#184,#510,#508,.T.);
#512=ORIENTED_EDGE('',*,*,#511,.F.);
#513=ORIENTED_EDGE('',*,*,#202,.F.);
#514=DIRECTION('',(0.,-0.866025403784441,0.499999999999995));
#515=VECTOR('',#514,1.);
#516=CARTESIAN_POINT('',(1.2,-2.77163859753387,1.14805029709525));
#517=LINE('',#516,#515);
#518=CARTESIAN_POINT('',(1.2,-2.77163859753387,1.14805029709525));
#519=VERTEX_POINT('',#518);
#520=EDGE_CURVE('E721',#519,#199,#517,.T.);
#521=ORIENTED_EDGE('',*,*,#520,.F.);
#522=EDGE_CURVE('E1398',#519,#510,#455,.T.);
#523=ORIENTED_EDGE('',*,*,#522,.T.);
#524=EDGE_LOOP('',(#512,#513,#521,#523));
#525=FACE_BOUND('',#524,.T.);
#526=ADVANCED_FACE('F1478',(#525),#433,.T.);
#527=DIRECTION('',(0.,1.,0.));
#528=VECTOR('',#527,1.);
#529=CARTESIAN_POINT('',(1.2,-2.97433458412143,0.391578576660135));
#530=LINE('',#529,#528);
#531=CARTESIAN_POINT('',(1.2,-2.97433458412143,0.391578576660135));
#532=VERTEX_POINT('',#531);
#533=EDGE_CURVE('E717',#221,#532,#530,.T.);
#534=ORIENTED_EDGE('',*,*,#533,.F.);
#535=ORIENTED_EDGE('',*,*,#243,.F.);
#536=DIRECTION('',(0.,-1.,0.));
#537=VECTOR('',#536,1.);
#538=CARTESIAN_POINT('',(1.2,-2.97433458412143,-0.391578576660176));
#539=LINE('',#538,#537);
#540=CARTESIAN_POINT('',(1.2,-2.97433458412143,-0.391578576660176));
#541=VERTEX_POINT('',#540);
#542=EDGE_CURVE('E742',#541,#240,#539,.T.);
#543=ORIENTED_EDGE('',*,*,#542,.F.);
#544=EDGE_CURVE('E1405',#541,#532,#455,.T.);
#545=ORIENTED_EDGE('',*,*,#544,.T.);
#546=EDGE_LOOP('',(#534,#535,#543,#545));
#547=FACE_BOUND('',#546,.T.);
#548=ADVANCED_FACE('F1470',(#547),#433,.T.);
#549=DIRECTION('',(0.,0.866025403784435,0.500000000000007));
#550=VECTOR('',#549,1.);
#551=CARTESIAN_POINT('',(1.2,-2.77163859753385,-1.14805029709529));
#552=LINE('',#551,#550);
#553=CARTESIAN_POINT('',(1.2,-2.77163859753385,-1.14805029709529));
#554=VERTEX_POINT('',#553);
#555=EDGE_CURVE('E735',#258,#554,#552,.T.);
#556=ORIENTED_EDGE('',*,*,#555,.F.);
#557=ORIENTED_EDGE('',*,*,#276,.F.);
#558=DIRECTION('',(0.,-0.866025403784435,-0.500000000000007));
#559=VECTOR('',#558,1.);
#560=CARTESIAN_POINT('',(1.2,-2.38006002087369,-1.82628428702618));
#561=LINE('',#560,#559);
#562=CARTESIAN_POINT('',(1.2,-2.38006002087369,-1.82628428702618));
#563=VERTEX_POINT('',#562);
#564=EDGE_CURVE('E758',#563,#273,#561,.T.);
#565=ORIENTED_EDGE('',*,*,#564,.F.);
#566=EDGE_CURVE('E1408',#563,#554,#455,.T.);
#567=ORIENTED_EDGE('',*,*,#566,.T.);
#568=EDGE_LOOP('',(#556,#557,#565,#567));
#569=FACE_BOUND('',#568,.T.);
#570=ADVANCED_FACE('F1586',(#569),#433,.T.);
#571=DIRECTION('',(0.,0.499999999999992,0.866025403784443));
#572=VECTOR('',#571,1.);
#573=CARTESIAN_POINT('',(1.2,-1.82628428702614,-2.38006002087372));
#574=LINE('',#573,#572);
#575=CARTESIAN_POINT('',(1.2,-1.82628428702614,-2.38006002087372));
#576=VERTEX_POINT('',#575);
#577=EDGE_CURVE('E755',#291,#576,#574,.T.);
#578=ORIENTED_EDGE('',*,*,#577,.F.);
#579=ORIENTED_EDGE('',*,*,#309,.F.);
#580=DIRECTION('',(0.,-0.499999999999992,-0.866025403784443));
#581=VECTOR('',#580,1.);
#582=CARTESIAN_POINT('',(1.2,-1.14805029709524,-2.77163859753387));
#583=LINE('',#582,#581);
#584=CARTESIAN_POINT('',(1.2,-1.14805029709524,-2.77163859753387));
#585=VERTEX_POINT('',#584);
#586=EDGE_CURVE('E773',#585,#306,#583,.T.);
#587=ORIENTED_EDGE('',*,*,#586,.F.);
#588=EDGE_CURVE('E1412',#585,#576,#455,.T.);
#589=ORIENTED_EDGE('',*,*,#588,.T.);
#590=EDGE_LOOP('',(#578,#579,#587,#589));
#591=FACE_BOUND('',#590,.T.);
#592=ADVANCED_FACE('F1421',(#591),#433,.T.);
#593=DIRECTION('',(0.,0.,1.));
#594=VECTOR('',#593,1.);
#595=CARTESIAN_POINT('',(1.2,-0.391578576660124,-2.97433458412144));
#596=LINE('',#595,#594);
#597=CARTESIAN_POINT('',(1.2,-0.391578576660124,-2.97433458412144));
#598=VERTEX_POINT('',#597);
#599=EDGE_CURVE('E768',#328,#598,#596,.T.);
#600=ORIENTED_EDGE('',*,*,#599,.F.);
#601=ORIENTED_EDGE('',*,*,#350,.F.);
#602=DIRECTION('',(0.,0.,-1.));
#603=VECTOR('',#602,1.);
#604=CARTESIAN_POINT('',(1.2,0.391578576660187,-2.97433458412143));
#605=LINE('',#604,#603);
#606=CARTESIAN_POINT('',(1.2,0.391578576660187,-2.97433458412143));
#607=VERTEX_POINT('',#606);
#608=EDGE_CURVE('E795',#607,#347,#605,.T.);
#609=ORIENTED_EDGE('',*,*,#608,.F.);
#610=EDGE_CURVE('E1255',#607,#598,#455,.T.);
#611=ORIENTED_EDGE('',*,*,#610,.T.);
#612=EDGE_LOOP('',(#600,#601,#609,#611));
#613=FACE_BOUND('',#612,.T.);
#614=ADVANCED_FACE('F1331',(#613),#433,.T.);
#615=DIRECTION('',(0.,-0.50000000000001,0.866025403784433));
#616=VECTOR('',#615,1.);
#617=CARTESIAN_POINT('',(1.2,1.1480502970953,-2.77163859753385));
#618=LINE('',#617,#616);
#619=CARTESIAN_POINT('',(1.2,1.1480502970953,-2.77163859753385));
#620=VERTEX_POINT('',#619);
#621=EDGE_CURVE('E787',#365,#620,#618,.T.);
#622=ORIENTED_EDGE('',*,*,#621,.F.);
#623=ORIENTED_EDGE('',*,*,#383,.F.);
#624=DIRECTION('',(0.,0.50000000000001,-0.866025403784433));
#625=VECTOR('',#624,1.);
#626=CARTESIAN_POINT('',(1.2,1.82628428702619,-2.38006002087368));
#627=LINE('',#626,#625);
#628=CARTESIAN_POINT('',(1.2,1.82628428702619,-2.38006002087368));
#629=VERTEX_POINT('',#628);
#630=EDGE_CURVE('E647',#629,#380,#627,.T.);
#631=ORIENTED_EDGE('',*,*,#630,.F.);
#632=EDGE_CURVE('E1251',#629,#620,#455,.T.);
#633=ORIENTED_EDGE('',*,*,#632,.T.);
#634=EDGE_LOOP('',(#622,#623,#631,#633));
#635=FACE_BOUND('',#634,.T.);
#636=ADVANCED_FACE('F1608',(#635),#433,.T.);
#637=DIRECTION('',(0.,-0.866025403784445,0.499999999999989));
#638=VECTOR('',#637,1.);
#639=CARTESIAN_POINT('',(1.2,2.38006002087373,-1.82628428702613));
#640=LINE('',#639,#638);
#641=CARTESIAN_POINT('',(1.2,2.70076760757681,-2.01144489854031));
#642=VERTEX_POINT('',#641);
#643=CARTESIAN_POINT('',(1.2,2.38006002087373,-1.82628428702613));
#644=VERTEX_POINT('',#643);
#645=EDGE_CURVE('E802',#642,#644,#640,.T.);
#646=ORIENTED_EDGE('',*,*,#645,.F.);
#647=CARTESIAN_POINT('',(1.2,3.09234618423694,-1.33321090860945));
#648=VERTEX_POINT('',#647);
#649=EDGE_CURVE('E978',#648,#642,#50,.T.);
#650=ORIENTED_EDGE('',*,*,#649,.F.);
#651=DIRECTION('',(0.,0.866025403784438,-0.500000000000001));
#652=VECTOR('',#651,1.);
#653=CARTESIAN_POINT('',(1.2,2.77163859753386,-1.14805029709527));
#654=LINE('',#653,#652);
#655=CARTESIAN_POINT('',(1.2,2.77163859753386,-1.14805029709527));
#656=VERTEX_POINT('',#655);
#657=EDGE_CURVE('E883',#656,#648,#654,.T.);
#658=ORIENTED_EDGE('',*,*,#657,.F.);
#659=EDGE_CURVE('E1240',#656,#644,#455,.T.);
#660=ORIENTED_EDGE('',*,*,#659,.T.);
#661=EDGE_LOOP('',(#646,#650,#658,#660));
#662=FACE_BOUND('',#661,.T.);
#663=ADVANCED_FACE('F960',(#662),#433,.T.);
#664=DIRECTION('',(0.,0.866025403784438,0.500000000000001));
#665=VECTOR('',#664,1.);
#666=CARTESIAN_POINT('',(1.2,2.3800600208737,1.82628428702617));
#667=LINE('',#666,#665);
#668=CARTESIAN_POINT('',(1.2,2.3800600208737,1.82628428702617));
#669=VERTEX_POINT('',#668);
#670=EDGE_CURVE('E659',#669,#43,#667,.T.);
#671=ORIENTED_EDGE('',*,*,#670,.F.);
#672=CARTESIAN_POINT('',(1.2,2.77163859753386,1.14805029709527));
#673=VERTEX_POINT('',#672);
#674=EDGE_CURVE('E1252',#669,#673,#455,.T.);
#675=ORIENTED_EDGE('',*,*,#674,.T.);
#676=DIRECTION('',(0.,-0.866025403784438,-0.500000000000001));
#677=VECTOR('',#676,1.);
#678=CARTESIAN_POINT('',(1.2,2.77163859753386,1.14805029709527));
#679=LINE('',#678,#677);
#680=EDGE_CURVE('E1279',#52,#673,#679,.T.);
#681=ORIENTED_EDGE('',*,*,#680,.F.);
#682=ORIENTED_EDGE('',*,*,#53,.F.);
#683=EDGE_LOOP('',(#671,#675,#681,#682));
#684=FACE_BOUND('',#683,.T.);
#685=ADVANCED_FACE('F948',(#684),#433,.T.);
#686=CARTESIAN_POINT('',(0.,0.,0.));
#687=DIRECTION('',(-1.,0.,0.));
#688=DIRECTION('',(0.,0.,1.));
#689=AXIS2_PLACEMENT_3D('',#686,#687,#688);
#690=PLANE('',#689);
#691=CARTESIAN_POINT('',(0.,0.,0.));
#692=DIRECTION('',(-1.,0.,0.));
#693=DIRECTION('',(0.,0.,1.));
#694=AXIS2_PLACEMENT_3D('',#691,#692,#693);
#695=CIRCLE('',#694,3.79746);
#696=CARTESIAN_POINT('',(0.,0.,3.79746));
#697=VERTEX_POINT('',#696);
#698=EDGE_CURVE('E1291',#697,#697,#695,.T.);
#699=ORIENTED_EDGE('',*,*,#698,.T.);
#700=EDGE_LOOP('',(#699));
#701=FACE_BOUND('',#700,.T.);
#702=ADVANCED_FACE('F41',(#701),#690,.T.);
#703=CARTESIAN_POINT('',(0.,0.,0.));
#704=DIRECTION('',(-1.,0.,0.));
#705=DIRECTION('',(0.,0.,1.));
#706=AXIS2_PLACEMENT_3D('',#703,#704,#705);
#707=CYLINDRICAL_SURFACE('',#706,3.79746);
#708=CARTESIAN_POINT('',(0.00508000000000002,0.,0.));
#709=DIRECTION('',(-1.,0.,0.));
#710=DIRECTION('',(0.,0.,1.));
#711=AXIS2_PLACEMENT_3D('',#708,#709,#710);
#712=CIRCLE('',#711,3.79746);
#713=CARTESIAN_POINT('',(0.00508000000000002,0.,3.79746));
#714=VERTEX_POINT('',#713);
#715=EDGE_CURVE('E1298',#714,#714,#712,.T.);
#716=ORIENTED_EDGE('',*,*,#715,.T.);
#717=EDGE_LOOP('',(#716));
#718=FACE_BOUND('',#717,.T.);
#719=ORIENTED_EDGE('',*,*,#698,.F.);
#720=EDGE_LOOP('',(#719));
#721=FACE_BOUND('',#720,.T.);
#722=ADVANCED_FACE('F2217',(#718,#721),#707,.T.);
#723=CARTESIAN_POINT('',(0.00508,3.80254,0.));
#724=DIRECTION('',(1.,0.,0.));
#725=DIRECTION('',(0.,0.,-1.));
#726=AXIS2_PLACEMENT_3D('',#723,#724,#725);
#727=PLANE('',#726);
#728=ORIENTED_EDGE('',*,*,#715,.F.);
#729=EDGE_LOOP('',(#728));
#730=FACE_BOUND('',#729,.T.);
#731=CARTESIAN_POINT('',(0.00507999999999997,0.,0.));
#732=DIRECTION('',(-1.,0.,0.));
#733=DIRECTION('',(0.,0.,1.));
#734=AXIS2_PLACEMENT_3D('',#731,#732,#733);
#735=CIRCLE('',#734,3.80254);
#736=CARTESIAN_POINT('',(0.00507999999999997,0.,3.80254));
#737=VERTEX_POINT('',#736);
#738=EDGE_CURVE('E990',#737,#737,#735,.T.);
#739=ORIENTED_EDGE('',*,*,#738,.T.);
#740=EDGE_LOOP('',(#739));
#741=FACE_BOUND('',#740,.T.);
#742=ADVANCED_FACE('F1631',(#730,#741),#727,.F.);
#743=CARTESIAN_POINT('',(0.30254,0.,0.));
#744=DIRECTION('',(-1.,0.,0.));
#745=DIRECTION('',(0.,0.,1.));
#746=AXIS2_PLACEMENT_3D('',#743,#744,#745);
#747=TOROIDAL_SURFACE('',#746,3.80254,0.29746);
#748=CARTESIAN_POINT('',(0.6,0.,0.));
#749=DIRECTION('',(-1.,0.,0.));
#750=DIRECTION('',(0.,0.,1.));
#751=AXIS2_PLACEMENT_3D('',#748,#749,#750);
#752=CIRCLE('',#751,3.80254);
#753=CARTESIAN_POINT('',(0.6,0.,3.80254));
#754=VERTEX_POINT('',#753);
#755=EDGE_CURVE('E981',#754,#754,#752,.T.);
#756=ORIENTED_EDGE('',*,*,#755,.T.);
#757=EDGE_LOOP('',(#756));
#758=FACE_BOUND('',#757,.T.);
#759=ORIENTED_EDGE('',*,*,#738,.F.);
#760=EDGE_LOOP('',(#759));
#761=FACE_BOUND('',#760,.T.);
#762=ADVANCED_FACE('F1629',(#758,#761),#747,.T.);
#763=CARTESIAN_POINT('',(0.6,3.80254,0.));
#764=DIRECTION('',(1.,0.,0.));
#765=DIRECTION('',(0.,0.,-1.));
#766=AXIS2_PLACEMENT_3D('',#763,#764,#765);
#767=PLANE('',#766);
#768=ORIENTED_EDGE('',*,*,#755,.F.);
#769=EDGE_LOOP('',(#768));
#770=FACE_BOUND('',#769,.T.);
#771=ORIENTED_EDGE('',*,*,#370,.T.);
#772=DIRECTION('',(0.,-0.50000000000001,0.866025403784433));
#773=VECTOR('',#772,1.);
#774=CARTESIAN_POINT('',(0.6,1.33321090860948,-3.09234618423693));
#775=LINE('',#774,#773);
#776=CARTESIAN_POINT('',(0.6,1.33321090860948,-3.09234618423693));
#777=VERTEX_POINT('',#776);
#778=EDGE_CURVE('E612',#363,#777,#775,.T.);
#779=ORIENTED_EDGE('',*,*,#778,.T.);
#780=CARTESIAN_POINT('',(0.6,0.,0.));
#781=DIRECTION('',(-1.,0.,0.));
#782=DIRECTION('',(0.,-0.866025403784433,-0.50000000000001));
#783=AXIS2_PLACEMENT_3D('',#780,#781,#782);
#784=CIRCLE('',#783,3.3675);
#785=CARTESIAN_POINT('',(0.6,0.391578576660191,-3.34465580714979));
#786=VERTEX_POINT('',#785);
#787=EDGE_CURVE('E614',#777,#786,#784,.T.);
#788=ORIENTED_EDGE('',*,*,#787,.T.);
#789=DIRECTION('',(0.,0.,-1.));
#790=VECTOR('',#789,1.);
#791=CARTESIAN_POINT('',(0.6,0.391578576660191,-3.34465580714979));
#792=LINE('',#791,#790);
#793=EDGE_CURVE('E617',#786,#332,#792,.T.);
#794=ORIENTED_EDGE('',*,*,#793,.T.);
#795=ORIENTED_EDGE('',*,*,#333,.T.);
#796=DIRECTION('',(0.,0.,1.));
#797=VECTOR('',#796,1.);
#798=CARTESIAN_POINT('',(0.6,-0.391578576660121,-3.34465580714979));
#799=LINE('',#798,#797);
#800=CARTESIAN_POINT('',(0.6,-0.391578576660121,-3.34465580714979));
#801=VERTEX_POINT('',#800);
#802=EDGE_CURVE('E596',#326,#801,#799,.T.);
#803=ORIENTED_EDGE('',*,*,#802,.T.);
#804=CARTESIAN_POINT('',(0.6,0.,0.));
#805=DIRECTION('',(-1.,0.,0.));
#806=DIRECTION('',(0.,-1.,0.));
#807=AXIS2_PLACEMENT_3D('',#804,#805,#806);
#808=CIRCLE('',#807,3.3675);
#809=CARTESIAN_POINT('',(0.6,-1.33321090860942,-3.09234618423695));
#810=VERTEX_POINT('',#809);
#811=EDGE_CURVE('E598',#801,#810,#808,.T.);
#812=ORIENTED_EDGE('',*,*,#811,.T.);
#813=DIRECTION('',(0.,-0.499999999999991,-0.866025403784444));
#814=VECTOR('',#813,1.);
#815=CARTESIAN_POINT('',(0.6,-1.33321090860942,-3.09234618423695));
#816=LINE('',#815,#814);
#817=EDGE_CURVE('E603',#810,#295,#816,.T.);
#818=ORIENTED_EDGE('',*,*,#817,.T.);
#819=ORIENTED_EDGE('',*,*,#296,.T.);
#820=DIRECTION('',(0.,0.499999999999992,0.866025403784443));
#821=VECTOR('',#820,1.);
#822=CARTESIAN_POINT('',(0.6,-2.01144489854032,-2.7007676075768));
#823=LINE('',#822,#821);
#824=CARTESIAN_POINT('',(0.6,-2.01144489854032,-2.7007676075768));
#825=VERTEX_POINT('',#824);
#826=EDGE_CURVE('E585',#289,#825,#823,.T.);
#827=ORIENTED_EDGE('',*,*,#826,.T.);
#828=CARTESIAN_POINT('',(0.6,0.,0.));
#829=DIRECTION('',(-1.,0.,0.));
#830=DIRECTION('',(0.,-0.866025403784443,0.499999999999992));
#831=AXIS2_PLACEMENT_3D('',#828,#829,#830);
#832=CIRCLE('',#831,3.3675);
#833=CARTESIAN_POINT('',(0.6,-2.70076760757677,-2.01144489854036));
#834=VERTEX_POINT('',#833);
#835=EDGE_CURVE('E590',#825,#834,#832,.T.);
#836=ORIENTED_EDGE('',*,*,#835,.T.);
#837=DIRECTION('',(0.,-0.866025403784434,-0.500000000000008));
#838=VECTOR('',#837,1.);
#839=CARTESIAN_POINT('',(0.6,-2.70076760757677,-2.01144489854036));
#840=LINE('',#839,#838);
#841=EDGE_CURVE('E592',#834,#262,#840,.T.);
#842=ORIENTED_EDGE('',*,*,#841,.T.);
#843=ORIENTED_EDGE('',*,*,#263,.T.);
#844=DIRECTION('',(0.,0.866025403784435,0.500000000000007));
#845=VECTOR('',#844,1.);
#846=CARTESIAN_POINT('',(0.6,-3.09234618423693,-1.33321090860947));
#847=LINE('',#846,#845);
#848=CARTESIAN_POINT('',(0.6,-3.09234618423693,-1.33321090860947));
#849=VERTEX_POINT('',#848);
#850=EDGE_CURVE('E575',#256,#849,#847,.T.);
#851=ORIENTED_EDGE('',*,*,#850,.T.);
#852=CARTESIAN_POINT('',(0.6,0.,0.));
#853=DIRECTION('',(-1.,0.,0.));
#854=DIRECTION('',(0.,-0.500000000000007,0.866025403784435));
#855=AXIS2_PLACEMENT_3D('',#852,#853,#854);
#856=CIRCLE('',#855,3.3675);
#857=CARTESIAN_POINT('',(0.6,-3.34465580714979,-0.391578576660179));
#858=VERTEX_POINT('',#857);
#859=EDGE_CURVE('E573',#849,#858,#856,.T.);
#860=ORIENTED_EDGE('',*,*,#859,.T.);
#861=DIRECTION('',(0.,-1.,0.));
#862=VECTOR('',#861,1.);
#863=CARTESIAN_POINT('',(0.6,-3.34465580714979,-0.391578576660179));
#864=LINE('',#863,#862);
#865=EDGE_CURVE('E579',#858,#225,#864,.T.);
#866=ORIENTED_EDGE('',*,*,#865,.T.);
#867=ORIENTED_EDGE('',*,*,#226,.T.);
#868=DIRECTION('',(0.,1.,0.));
#869=VECTOR('',#868,1.);
#870=CARTESIAN_POINT('',(0.6,-3.34465580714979,0.391578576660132));
#871=LINE('',#870,#869);
#872=CARTESIAN_POINT('',(0.6,-3.34465580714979,0.391578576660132));
#873=VERTEX_POINT('',#872);
#874=EDGE_CURVE('E559',#219,#873,#871,.T.);
#875=ORIENTED_EDGE('',*,*,#874,.T.);
#876=CARTESIAN_POINT('',(0.6,0.,0.));
#877=DIRECTION('',(-1.,0.,0.));
#878=DIRECTION('',(0.,0.,1.));
#879=AXIS2_PLACEMENT_3D('',#876,#877,#878);
#880=CIRCLE('',#879,3.3675);
#881=CARTESIAN_POINT('',(0.6,-3.09234618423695,1.33321090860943));
#882=VERTEX_POINT('',#881);
#883=EDGE_CURVE('E561',#873,#882,#880,.T.);
#884=ORIENTED_EDGE('',*,*,#883,.T.);
#885=DIRECTION('',(0.,-0.866025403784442,0.499999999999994));
#886=VECTOR('',#885,1.);
#887=CARTESIAN_POINT('',(0.6,-3.09234618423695,1.33321090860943));
#888=LINE('',#887,#886);
#889=EDGE_CURVE('E564',#882,#188,#888,.T.);
#890=ORIENTED_EDGE('',*,*,#889,.T.);
#891=ORIENTED_EDGE('',*,*,#189,.T.);
#892=DIRECTION('',(0.,0.866025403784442,-0.499999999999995));
#893=VECTOR('',#892,1.);
#894=CARTESIAN_POINT('',(0.6,-2.7007676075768,2.01144489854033));
#895=LINE('',#894,#893);
#896=CARTESIAN_POINT('',(0.6,-2.7007676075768,2.01144489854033));
#897=VERTEX_POINT('',#896);
#898=EDGE_CURVE('E547',#182,#897,#895,.T.);
#899=ORIENTED_EDGE('',*,*,#898,.T.);
#900=CARTESIAN_POINT('',(0.6,0.,0.));
#901=DIRECTION('',(-1.,0.,0.));
#902=DIRECTION('',(0.,0.499999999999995,0.866025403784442));
#903=AXIS2_PLACEMENT_3D('',#900,#901,#902);
#904=CIRCLE('',#903,3.3675);
#905=CARTESIAN_POINT('',(0.6,-2.01144489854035,2.70076760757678));
#906=VERTEX_POINT('',#905);
#907=EDGE_CURVE('E549',#897,#906,#904,.T.);
#908=ORIENTED_EDGE('',*,*,#907,.T.);
#909=DIRECTION('',(0.,-0.500000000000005,0.866025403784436));
#910=VECTOR('',#909,1.);
#911=CARTESIAN_POINT('',(0.6,-2.01144489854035,2.70076760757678));
#912=LINE('',#911,#910);
#913=EDGE_CURVE('E552',#906,#155,#912,.T.);
#914=ORIENTED_EDGE('',*,*,#913,.T.);
#915=ORIENTED_EDGE('',*,*,#156,.T.);
#916=DIRECTION('',(0.,0.500000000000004,-0.866025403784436));
#917=VECTOR('',#916,1.);
#918=CARTESIAN_POINT('',(0.6,-1.33321090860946,3.09234618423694));
#919=LINE('',#918,#917);
#920=CARTESIAN_POINT('',(0.6,-1.33321090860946,3.09234618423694));
#921=VERTEX_POINT('',#920);
#922=EDGE_CURVE('E531',#149,#921,#919,.T.);
#923=ORIENTED_EDGE('',*,*,#922,.T.);
#924=CARTESIAN_POINT('',(0.6,0.,0.));
#925=DIRECTION('',(-1.,0.,0.));
#926=DIRECTION('',(0.,0.866025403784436,0.500000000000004));
#927=AXIS2_PLACEMENT_3D('',#924,#925,#926);
#928=CIRCLE('',#927,3.3675);
#929=CARTESIAN_POINT('',(0.6,-0.391578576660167,3.34465580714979));
#930=VERTEX_POINT('',#929);
#931=EDGE_CURVE('E533',#921,#930,#928,.T.);
#932=ORIENTED_EDGE('',*,*,#931,.T.);
#933=DIRECTION('',(0.,0.,1.));
#934=VECTOR('',#933,1.);
#935=CARTESIAN_POINT('',(0.6,-0.391578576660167,3.34465580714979));
#936=LINE('',#935,#934);
#937=EDGE_CURVE('E538',#930,#118,#936,.T.);
#938=ORIENTED_EDGE('',*,*,#937,.T.);
#939=ORIENTED_EDGE('',*,*,#119,.T.);
#940=DIRECTION('',(0.,0.,-1.));
#941=VECTOR('',#940,1.);
#942=CARTESIAN_POINT('',(0.6,0.391578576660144,3.34465580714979));
#943=LINE('',#942,#941);
#944=CARTESIAN_POINT('',(0.6,0.391578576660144,3.34465580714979));
#945=VERTEX_POINT('',#944);
#946=EDGE_CURVE('E521',#112,#945,#943,.T.);
#947=ORIENTED_EDGE('',*,*,#946,.T.);
#948=CARTESIAN_POINT('',(0.6,0.,0.));
#949=DIRECTION('',(-1.,0.,0.));
#950=DIRECTION('',(0.,1.,0.));
#951=AXIS2_PLACEMENT_3D('',#948,#949,#950);
#952=CIRCLE('',#951,3.3675);
#953=CARTESIAN_POINT('',(0.6,1.33321090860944,3.09234618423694));
#954=VERTEX_POINT('',#953);
#955=EDGE_CURVE('E522',#945,#954,#952,.T.);
#956=ORIENTED_EDGE('',*,*,#955,.T.);
#957=DIRECTION('',(0.,0.499999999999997,0.86602540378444));
#958=VECTOR('',#957,1.);
#959=CARTESIAN_POINT('',(0.6,1.33321090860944,3.09234618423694));
#960=LINE('',#959,#958);
#961=EDGE_CURVE('E530',#954,#81,#960,.T.);
#962=ORIENTED_EDGE('',*,*,#961,.T.);
#963=ORIENTED_EDGE('',*,*,#82,.T.);
#964=DIRECTION('',(0.,-0.499999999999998,-0.86602540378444));
#965=VECTOR('',#964,1.);
#966=CARTESIAN_POINT('',(0.6,2.01144489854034,2.70076760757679));
#967=LINE('',#966,#965);
#968=CARTESIAN_POINT('',(0.6,2.01144489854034,2.70076760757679));
#969=VERTEX_POINT('',#968);
#970=EDGE_CURVE('E493',#75,#969,#967,.T.);
#971=ORIENTED_EDGE('',*,*,#970,.T.);
#972=CARTESIAN_POINT('',(0.6,0.,0.));
#973=DIRECTION('',(-1.,0.,0.));
#974=DIRECTION('',(0.,0.86602540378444,-0.499999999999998));
#975=AXIS2_PLACEMENT_3D('',#972,#973,#974);
#976=CIRCLE('',#975,3.3675);
#977=CARTESIAN_POINT('',(0.6,2.70076760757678,2.01144489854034));
#978=VERTEX_POINT('',#977);
#979=EDGE_CURVE('E500',#969,#978,#976,.T.);
#980=ORIENTED_EDGE('',*,*,#979,.T.);
#981=DIRECTION('',(0.,0.866025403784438,0.500000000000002));
#982=VECTOR('',#981,1.);
#983=CARTESIAN_POINT('',(0.6,2.70076760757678,2.01144489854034));
#984=LINE('',#983,#982);
#985=EDGE_CURVE('E515',#978,#30,#984,.T.);
#986=ORIENTED_EDGE('',*,*,#985,.T.);
#987=ORIENTED_EDGE('',*,*,#33,.T.);
#988=DIRECTION('',(0.,-0.866025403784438,-0.500000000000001));
#989=VECTOR('',#988,1.);
#990=CARTESIAN_POINT('',(0.6,3.09234618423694,1.33321090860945));
#991=LINE('',#990,#989);
#992=CARTESIAN_POINT('',(0.6,3.09234618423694,1.33321090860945));
#993=VERTEX_POINT('',#992);
#994=EDGE_CURVE('E518',#32,#993,#991,.T.);
#995=ORIENTED_EDGE('',*,*,#994,.T.);
#996=CARTESIAN_POINT('',(0.6,0.,0.));
#997=DIRECTION('',(-1.,0.,0.));
#998=DIRECTION('',(0.,0.500000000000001,-0.866025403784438));
#999=AXIS2_PLACEMENT_3D('',#996,#997,#998);
#1000=CIRCLE('',#999,3.3675);
#1001=CARTESIAN_POINT('',(0.6,3.34465580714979,0.391578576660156));
#1002=VERTEX_POINT('',#1001);
#1003=EDGE_CURVE('E640',#993,#1002,#1000,.T.);
#1004=ORIENTED_EDGE('',*,*,#1003,.T.);
#1005=DIRECTION('',(0.,1.,0.));
#1006=VECTOR('',#1005,1.);
#1007=CARTESIAN_POINT('',(0.6,3.34465580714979,0.391578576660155));
#1008=LINE('',#1007,#1006);
#1009=EDGE_CURVE('E639',#1002,#389,#1008,.T.);
#1010=ORIENTED_EDGE('',*,*,#1009,.T.);
#1011=ORIENTED_EDGE('',*,*,#392,.T.);
#1012=DIRECTION('',(0.,-1.,0.));
#1013=VECTOR('',#1012,1.);
#1014=CARTESIAN_POINT('',(0.6,3.34465580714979,-0.391578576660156));
#1015=LINE('',#1014,#1013);
#1016=CARTESIAN_POINT('',(0.6,3.34465580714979,-0.391578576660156));
#1017=VERTEX_POINT('',#1016);
#1018=EDGE_CURVE('E864',#391,#1017,#1015,.T.);
#1019=ORIENTED_EDGE('',*,*,#1018,.T.);
#1020=CARTESIAN_POINT('',(0.6,0.,0.));
#1021=DIRECTION('',(-1.,0.,0.));
#1022=DIRECTION('',(0.,0.,-1.));
#1023=AXIS2_PLACEMENT_3D('',#1020,#1021,#1022);
#1024=CIRCLE('',#1023,3.3675);
#1025=CARTESIAN_POINT('',(0.6,3.09234618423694,-1.33321090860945));
#1026=VERTEX_POINT('',#1025);
#1027=EDGE_CURVE('E872',#1017,#1026,#1024,.T.);
#1028=ORIENTED_EDGE('',*,*,#1027,.T.);
#1029=DIRECTION('',(0.,0.866025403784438,-0.5));
#1030=VECTOR('',#1029,1.);
#1031=CARTESIAN_POINT('',(0.6,3.09234618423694,-1.33321090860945));
#1032=LINE('',#1031,#1030);
#1033=CARTESIAN_POINT('',(0.6,3.41256848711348,-1.51809134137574));
#1034=VERTEX_POINT('',#1033);
#1035=EDGE_CURVE('E871',#1026,#1034,#1032,.T.);
#1036=ORIENTED_EDGE('',*,*,#1035,.T.);
#1037=CARTESIAN_POINT('',(0.6,3.02098991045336,-2.1963253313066));
#1038=VERTEX_POINT('',#1037);
#1039=EDGE_CURVE('E980',#1034,#1038,#28,.T.);
#1040=ORIENTED_EDGE('',*,*,#1039,.T.);
#1041=DIRECTION('',(0.,-0.866025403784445,0.499999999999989));
#1042=VECTOR('',#1041,1.);
#1043=CARTESIAN_POINT('',(0.6,2.70076760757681,-2.01144489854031));
#1044=LINE('',#1043,#1042);
#1045=CARTESIAN_POINT('',(0.6,2.70076760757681,-2.01144489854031));
#1046=VERTEX_POINT('',#1045);
#1047=EDGE_CURVE('E624',#1038,#1046,#1044,.T.);
#1048=ORIENTED_EDGE('',*,*,#1047,.T.);
#1049=CARTESIAN_POINT('',(0.6,0.,0.));
#1050=DIRECTION('',(-1.,0.,0.));
#1051=DIRECTION('',(0.,-0.499999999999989,-0.866025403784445));
#1052=AXIS2_PLACEMENT_3D('',#1049,#1050,#1051);
#1053=CIRCLE('',#1052,3.3675);
#1054=CARTESIAN_POINT('',(0.6,2.01144489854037,-2.70076760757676));
#1055=VERTEX_POINT('',#1054);
#1056=EDGE_CURVE('E626',#1046,#1055,#1053,.T.);
#1057=ORIENTED_EDGE('',*,*,#1056,.T.);
#1058=DIRECTION('',(0.,0.500000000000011,-0.866025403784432));
#1059=VECTOR('',#1058,1.);
#1060=CARTESIAN_POINT('',(0.6,2.01144489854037,-2.70076760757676));
#1061=LINE('',#1060,#1059);
#1062=EDGE_CURVE('E627',#1055,#369,#1061,.T.);
#1063=ORIENTED_EDGE('',*,*,#1062,.T.);
#1064=EDGE_LOOP('',(#771,#779,#788,#794,#795,#803,#812,#818,#819,#827,#836,#842,#843,#851,#860,
#866,#867,#875,#884,#890,#891,#899,#908,#914,#915,#923,#932,#938,#939,#947,#956,#962,#963,#971,
#980,#986,#987,#995,#1004,#1010,#1011,#1019,#1028,#1036,#1040,#1048,#1057,#1063));
#1065=FACE_BOUND('',#1064,.T.);
#1066=ADVANCED_FACE('F494',(#770,#1065),#767,.T.);
#1067=CARTESIAN_POINT('',(0.5998,3.02109658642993,-2.19638692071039));
#1068=CARTESIAN_POINT('',(0.67480487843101,2.98109143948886,-2.17328993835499));
#1069=CARTESIAN_POINT('',(0.74980487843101,2.94107943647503,-2.15018899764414));
#1070=CARTESIAN_POINT('',(0.94994691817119,2.83427974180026,-2.0885281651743));
#1071=CARTESIAN_POINT('',(1.07508025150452,2.76747981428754,-2.04996120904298));
#1072=CARTESIAN_POINT('',(1.2002,2.70066079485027,-2.01138323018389));
#1073=B_SPLINE_CURVE_WITH_KNOTS('',3,(#1067,#1068,#1069,#1070,#1071,#1072),.UNSPECIFIED.,.F.,
.F.,(4,2,4),(0.,0.264266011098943,0.705255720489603),.UNSPECIFIED.);
#1074=EDGE_CURVE('E821',#1038,#642,#1073,.T.);
#1075=ORIENTED_EDGE('',*,*,#1074,.F.);
#1076=ORIENTED_EDGE('',*,*,#1039,.F.);
#1077=CARTESIAN_POINT('',(1.2002,3.0922393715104,-1.33314924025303));
#1078=CARTESIAN_POINT('',(1.07508025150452,3.15905839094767,-1.37172721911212));
#1079=CARTESIAN_POINT('',(0.949946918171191,3.22585831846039,-1.41029417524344));
#1080=CARTESIAN_POINT('',(0.74980487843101,3.33265801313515,-1.47195500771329));
#1081=CARTESIAN_POINT('',(0.67480487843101,3.37267001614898,-1.49505594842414));
#1082=CARTESIAN_POINT('',(0.5998,3.41267516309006,-1.51815293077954));
#1083=B_SPLINE_CURVE_WITH_KNOTS('',3,(#1077,#1078,#1079,#1080,#1081,#1082),.UNSPECIFIED.,.F.,
.F.,(4,2,4),(0.,0.44098970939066,0.705255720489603),.UNSPECIFIED.);
#1084=EDGE_CURVE('E898',#648,#1034,#1083,.T.);
#1085=ORIENTED_EDGE('',*,*,#1084,.F.);
#1086=ORIENTED_EDGE('',*,*,#649,.T.);
#1087=EDGE_LOOP('',(#1075,#1076,#1085,#1086));
#1088=FACE_BOUND('',#1087,.T.);
#1089=ADVANCED_FACE('F828',(#1088),#23,.T.);
#1090=DIRECTION('',(0.,1.,0.));
#1091=VECTOR('',#1090,1.);
#1092=CARTESIAN_POINT('',(1.2,2.97433458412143,0.391578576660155));
#1093=LINE('',#1092,#1091);
#1094=CARTESIAN_POINT('',(1.2,2.97433458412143,0.391578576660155));
#1095=VERTEX_POINT('',#1094);
#1096=EDGE_CURVE('E1278',#1095,#406,#1093,.T.);
#1097=ORIENTED_EDGE('',*,*,#1096,.F.);
#1098=CARTESIAN_POINT('',(1.2,2.97433458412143,-0.391578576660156));
#1099=VERTEX_POINT('',#1098);
#1100=EDGE_CURVE('E1254',#1095,#1099,#455,.T.);
#1101=ORIENTED_EDGE('',*,*,#1100,.T.);
#1102=DIRECTION('',(0.,-1.,0.));
#1103=VECTOR('',#1102,1.);
#1104=CARTESIAN_POINT('',(1.2,2.97433458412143,-0.391578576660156));
#1105=LINE('',#1104,#1103);
#1106=EDGE_CURVE('E890',#410,#1099,#1105,.T.);
#1107=ORIENTED_EDGE('',*,*,#1106,.F.);
#1108=ORIENTED_EDGE('',*,*,#411,.F.);
#1109=EDGE_LOOP('',(#1097,#1101,#1107,#1108));
#1110=FACE_BOUND('',#1109,.T.);
#1111=ADVANCED_FACE('F943',(#1110),#433,.T.);
#1112=CARTESIAN_POINT('',(0.,0.,0.));
#1113=DIRECTION('',(-1.,0.,0.));
#1114=DIRECTION('',(0.,0.,1.));
#1115=AXIS2_PLACEMENT_3D('',#1112,#1113,#1114);
#1116=CYLINDRICAL_SURFACE('',#1115,3.);
#1117=CARTESIAN_POINT('',(12.92,0.,0.));
#1118=DIRECTION('',(-1.,0.,0.));
#1119=DIRECTION('',(0.,0.,1.));
#1120=AXIS2_PLACEMENT_3D('',#1117,#1118,#1119);
#1121=CIRCLE('',#1120,3.);
#1122=CARTESIAN_POINT('',(12.92,0.,3.));
#1123=VERTEX_POINT('',#1122);
#1124=EDGE_CURVE('E1257',#1123,#1123,#1121,.T.);
#1125=ORIENTED_EDGE('',*,*,#1124,.T.);
#1126=EDGE_LOOP('',(#1125));
#1127=FACE_BOUND('',#1126,.T.);
#1128=ORIENTED_EDGE('',*,*,#659,.F.);
#1129=DIRECTION('',(1.,0.,0.));
#1130=VECTOR('',#1129,1.);
#1131=CARTESIAN_POINT('',(0.825,2.77163859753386,-1.14805029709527));
#1132=LINE('',#1131,#1130);
#1133=CARTESIAN_POINT('',(0.825,2.77163859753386,-1.14805029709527));
#1134=VERTEX_POINT('',#1133);
#1135=EDGE_CURVE('E895',#1134,#656,#1132,.T.);
#1136=ORIENTED_EDGE('',*,*,#1135,.F.);
#1137=CARTESIAN_POINT('',(0.825,0.,0.));
#1138=DIRECTION('',(-1.,0.,0.));
#1139=DIRECTION('',(0.,0.,-1.));
#1140=AXIS2_PLACEMENT_3D('',#1137,#1138,#1139);
#1141=CIRCLE('',#1140,3.);
#1142=CARTESIAN_POINT('',(0.825,2.97433458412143,-0.391578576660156));
#1143=VERTEX_POINT('',#1142);
#1144=EDGE_CURVE('E881',#1143,#1134,#1141,.T.);
#1145=ORIENTED_EDGE('',*,*,#1144,.F.);
#1146=DIRECTION('',(1.,0.,0.));
#1147=VECTOR('',#1146,1.);
#1148=CARTESIAN_POINT('',(0.825,2.97433458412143,-0.391578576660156));
#1149=LINE('',#1148,#1147);
#1150=EDGE_CURVE('E896',#1143,#1099,#1149,.T.);
#1151=ORIENTED_EDGE('',*,*,#1150,.T.);
#1152=ORIENTED_EDGE('',*,*,#1100,.F.);
#1153=DIRECTION('',(1.,0.,0.));
#1154=VECTOR('',#1153,1.);
#1155=CARTESIAN_POINT('',(0.825,2.97433458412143,0.391578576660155));
#1156=LINE('',#1155,#1154);
#1157=CARTESIAN_POINT('',(0.825,2.97433458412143,0.391578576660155));
#1158=VERTEX_POINT('',#1157);
#1159=EDGE_CURVE('E1282',#1158,#1095,#1156,.T.);
#1160=ORIENTED_EDGE('',*,*,#1159,.F.);
#1161=CARTESIAN_POINT('',(0.825,0.,0.));
#1162=DIRECTION('',(-1.,0.,0.));
#1163=DIRECTION('',(0.,0.500000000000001,-0.866025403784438));
#1164=AXIS2_PLACEMENT_3D('',#1161,#1162,#1163);
#1165=CIRCLE('',#1164,3.);
#1166=CARTESIAN_POINT('',(0.825,2.77163859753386,1.14805029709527));
#1167=VERTEX_POINT('',#1166);
#1168=EDGE_CURVE('E1373',#1167,#1158,#1165,.T.);
#1169=ORIENTED_EDGE('',*,*,#1168,.F.);
#1170=DIRECTION('',(1.,0.,0.));
#1171=VECTOR('',#1170,1.);
#1172=CARTESIAN_POINT('',(0.825,2.77163859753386,1.14805029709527));
#1173=LINE('',#1172,#1171);
#1174=EDGE_CURVE('E1548',#1167,#673,#1173,.T.);
#1175=ORIENTED_EDGE('',*,*,#1174,.T.);
#1176=ORIENTED_EDGE('',*,*,#674,.F.);
#1177=DIRECTION('',(1.,0.,0.));
#1178=VECTOR('',#1177,1.);
#1179=CARTESIAN_POINT('',(0.825,2.3800600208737,1.82628428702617));
#1180=LINE('',#1179,#1178);
#1181=CARTESIAN_POINT('',(0.825,2.3800600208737,1.82628428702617));
#1182=VERTEX_POINT('',#1181);
#1183=EDGE_CURVE('E660',#1182,#669,#1180,.T.);
#1184=ORIENTED_EDGE('',*,*,#1183,.F.);
#1185=CARTESIAN_POINT('',(0.825,0.,0.));
#1186=DIRECTION('',(-1.,0.,0.));
#1187=DIRECTION('',(0.,0.86602540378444,-0.499999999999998));
#1188=AXIS2_PLACEMENT_3D('',#1185,#1186,#1187);
#1189=CIRCLE('',#1188,3.);
#1190=CARTESIAN_POINT('',(0.825,1.82628428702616,2.38006002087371));
#1191=VERTEX_POINT('',#1190);
#1192=EDGE_CURVE('E648',#1191,#1182,#1189,.T.);
#1193=ORIENTED_EDGE('',*,*,#1192,.F.);
#1194=DIRECTION('',(1.,0.,0.));
#1195=VECTOR('',#1194,1.);
#1196=CARTESIAN_POINT('',(0.825,1.82628428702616,2.38006002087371));
#1197=LINE('',#1196,#1195);
#1198=EDGE_CURVE('E53',#1191,#439,#1197,.T.);
#1199=ORIENTED_EDGE('',*,*,#1198,.T.);
#1200=ORIENTED_EDGE('',*,*,#456,.F.);
#1201=DIRECTION('',(1.,0.,0.));
#1202=VECTOR('',#1201,1.);
#1203=CARTESIAN_POINT('',(0.825,1.14805029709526,2.77163859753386));
#1204=LINE('',#1203,#1202);
#1205=CARTESIAN_POINT('',(0.825,1.14805029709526,2.77163859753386));
#1206=VERTEX_POINT('',#1205);
#1207=EDGE_CURVE('E672',#1206,#448,#1204,.T.);
#1208=ORIENTED_EDGE('',*,*,#1207,.F.);
#1209=CARTESIAN_POINT('',(0.825,0.,0.));
#1210=DIRECTION('',(-1.,0.,0.));
#1211=DIRECTION('',(0.,1.,0.));
#1212=AXIS2_PLACEMENT_3D('',#1209,#1210,#1211);
#1213=CIRCLE('',#1212,3.);
#1214=CARTESIAN_POINT('',(0.825,0.391578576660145,2.97433458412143));
#1215=VERTEX_POINT('',#1214);
#1216=EDGE_CURVE('E664',#1215,#1206,#1213,.T.);
#1217=ORIENTED_EDGE('',*,*,#1216,.F.);
#1218=DIRECTION('',(1.,0.,0.));
#1219=VECTOR('',#1218,1.);
#1220=CARTESIAN_POINT('',(0.825,0.391578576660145,2.97433458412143));
#1221=LINE('',#1220,#1219);
#1222=EDGE_CURVE('E61',#1215,#466,#1221,.T.);
#1223=ORIENTED_EDGE('',*,*,#1222,.T.);
#1224=ORIENTED_EDGE('',*,*,#478,.F.);
#1225=DIRECTION('',(1.,0.,0.));
#1226=VECTOR('',#1225,1.);
#1227=CARTESIAN_POINT('',(0.825,-0.391578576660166,2.97433458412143));
#1228=LINE('',#1227,#1226);
#1229=CARTESIAN_POINT('',(0.825,-0.391578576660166,2.97433458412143));
#1230=VERTEX_POINT('',#1229);
#1231=EDGE_CURVE('E689',#1230,#475,#1228,.T.);
#1232=ORIENTED_EDGE('',*,*,#1231,.F.);
#1233=CARTESIAN_POINT('',(0.825,0.,0.));
#1234=DIRECTION('',(-1.,0.,0.));
#1235=DIRECTION('',(0.,0.866025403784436,0.500000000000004));
#1236=AXIS2_PLACEMENT_3D('',#1233,#1234,#1235);
#1237=CIRCLE('',#1236,3.);
#1238=CARTESIAN_POINT('',(0.825,-1.14805029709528,2.77163859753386));
#1239=VERTEX_POINT('',#1238);
#1240=EDGE_CURVE('E678',#1239,#1230,#1237,.T.);
#1241=ORIENTED_EDGE('',*,*,#1240,.F.);
#1242=DIRECTION('',(1.,0.,0.));
#1243=VECTOR('',#1242,1.);
#1244=CARTESIAN_POINT('',(0.825,-1.14805029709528,2.77163859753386));
#1245=LINE('',#1244,#1243);
#1246=EDGE_CURVE('E677',#1239,#488,#1245,.T.);
#1247=ORIENTED_EDGE('',*,*,#1246,.T.);
#1248=ORIENTED_EDGE('',*,*,#500,.F.);
#1249=DIRECTION('',(1.,0.,0.));
#1250=VECTOR('',#1249,1.);
#1251=CARTESIAN_POINT('',(0.825,-1.82628428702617,2.3800600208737));
#1252=LINE('',#1251,#1250);
#1253=CARTESIAN_POINT('',(0.825,-1.82628428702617,2.3800600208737));
#1254=VERTEX_POINT('',#1253);
#1255=EDGE_CURVE('E707',#1254,#497,#1252,.T.);
#1256=ORIENTED_EDGE('',*,*,#1255,.F.);
#1257=CARTESIAN_POINT('',(0.825,0.,0.));
#1258=DIRECTION('',(-1.,0.,0.));
#1259=DIRECTION('',(0.,0.499999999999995,0.866025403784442));
#1260=AXIS2_PLACEMENT_3D('',#1257,#1258,#1259);
#1261=CIRCLE('',#1260,3.);
#1262=CARTESIAN_POINT('',(0.825,-2.38006002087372,1.82628428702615));
#1263=VERTEX_POINT('',#1262);
#1264=EDGE_CURVE('E700',#1263,#1254,#1261,.T.);
#1265=ORIENTED_EDGE('',*,*,#1264,.F.);
#1266=DIRECTION('',(1.,0.,0.));
#1267=VECTOR('',#1266,1.);
#1268=CARTESIAN_POINT('',(0.825,-2.38006002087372,1.82628428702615));
#1269=LINE('',#1268,#1267);
#1270=EDGE_CURVE('E695',#1263,#510,#1269,.T.);
#1271=ORIENTED_EDGE('',*,*,#1270,.T.);
#1272=ORIENTED_EDGE('',*,*,#522,.F.);
#1273=DIRECTION('',(1.,0.,0.));
#1274=VECTOR('',#1273,1.);
#1275=CARTESIAN_POINT('',(0.825,-2.77163859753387,1.14805029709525));
#1276=LINE('',#1275,#1274);
#1277=CARTESIAN_POINT('',(0.825,-2.77163859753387,1.14805029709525));
#1278=VERTEX_POINT('',#1277);
#1279=EDGE_CURVE('E724',#1278,#519,#1276,.T.);
#1280=ORIENTED_EDGE('',*,*,#1279,.F.);
#1281=CARTESIAN_POINT('',(0.825,0.,0.));
#1282=DIRECTION('',(-1.,0.,0.));
#1283=DIRECTION('',(0.,0.,1.));
#1284=AXIS2_PLACEMENT_3D('',#1281,#1282,#1283);
#1285=CIRCLE('',#1284,3.);
#1286=CARTESIAN_POINT('',(0.825,-2.97433458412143,0.391578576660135));
#1287=VERTEX_POINT('',#1286);
#1288=EDGE_CURVE('E713',#1287,#1278,#1285,.T.);
#1289=ORIENTED_EDGE('',*,*,#1288,.F.);
#1290=DIRECTION('',(1.,0.,0.));
#1291=VECTOR('',#1290,1.);
#1292=CARTESIAN_POINT('',(0.825,-2.97433458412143,0.391578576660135));
#1293=LINE('',#1292,#1291);
#1294=EDGE_CURVE('E706',#1287,#532,#1293,.T.);
#1295=ORIENTED_EDGE('',*,*,#1294,.T.);
#1296=ORIENTED_EDGE('',*,*,#544,.F.);
#1297=DIRECTION('',(1.,0.,0.));
#1298=VECTOR('',#1297,1.);
#1299=CARTESIAN_POINT('',(0.825,-2.97433458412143,-0.391578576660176));
#1300=LINE('',#1299,#1298);
#1301=CARTESIAN_POINT('',(0.825,-2.97433458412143,-0.391578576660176));
#1302=VERTEX_POINT('',#1301);
#1303=EDGE_CURVE('E739',#1302,#541,#1300,.T.);
#1304=ORIENTED_EDGE('',*,*,#1303,.F.);
#1305=CARTESIAN_POINT('',(0.825,0.,0.));
#1306=DIRECTION('',(-1.,0.,0.));
#1307=DIRECTION('',(0.,-0.500000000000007,0.866025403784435));
#1308=AXIS2_PLACEMENT_3D('',#1305,#1306,#1307);
#1309=CIRCLE('',#1308,3.);
#1310=CARTESIAN_POINT('',(0.825,-2.77163859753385,-1.14805029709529));
#1311=VERTEX_POINT('',#1310);
#1312=EDGE_CURVE('E731',#1311,#1302,#1309,.T.);
#1313=ORIENTED_EDGE('',*,*,#1312,.F.);
#1314=DIRECTION('',(1.,0.,0.));
#1315=VECTOR('',#1314,1.);
#1316=CARTESIAN_POINT('',(0.825,-2.77163859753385,-1.14805029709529));
#1317=LINE('',#1316,#1315);
#1318=EDGE_CURVE('E727',#1311,#554,#1317,.T.);
#1319=ORIENTED_EDGE('',*,*,#1318,.T.);
#1320=ORIENTED_EDGE('',*,*,#566,.F.);
#1321=DIRECTION('',(1.,0.,0.));
#1322=VECTOR('',#1321,1.);
#1323=CARTESIAN_POINT('',(0.825,-2.38006002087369,-1.82628428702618));
#1324=LINE('',#1323,#1322);
#1325=CARTESIAN_POINT('',(0.825,-2.38006002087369,-1.82628428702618));
#1326=VERTEX_POINT('',#1325);
#1327=EDGE_CURVE('E760',#1326,#563,#1324,.T.);
#1328=ORIENTED_EDGE('',*,*,#1327,.F.);
#1329=CARTESIAN_POINT('',(0.825,0.,0.));
#1330=DIRECTION('',(-1.,0.,0.));
#1331=DIRECTION('',(0.,-0.866025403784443,0.499999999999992));
#1332=AXIS2_PLACEMENT_3D('',#1329,#1330,#1331);
#1333=CIRCLE('',#1332,3.);
#1334=CARTESIAN_POINT('',(0.825,-1.82628428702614,-2.38006002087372));
#1335=VERTEX_POINT('',#1334);
#1336=EDGE_CURVE('E746',#1335,#1326,#1333,.T.);
#1337=ORIENTED_EDGE('',*,*,#1336,.F.);
#1338=DIRECTION('',(1.,0.,0.));
#1339=VECTOR('',#1338,1.);
#1340=CARTESIAN_POINT('',(0.825,-1.82628428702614,-2.38006002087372));
#1341=LINE('',#1340,#1339);
#1342=EDGE_CURVE('E744',#1335,#576,#1341,.T.);
#1343=ORIENTED_EDGE('',*,*,#1342,.T.);
#1344=ORIENTED_EDGE('',*,*,#588,.F.);
#1345=DIRECTION('',(1.,0.,0.));
#1346=VECTOR('',#1345,1.);
#1347=CARTESIAN_POINT('',(0.825,-1.14805029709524,-2.77163859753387));
#1348=LINE('',#1347,#1346);
#1349=CARTESIAN_POINT('',(0.825,-1.14805029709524,-2.77163859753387));
#1350=VERTEX_POINT('',#1349);
#1351=EDGE_CURVE('E771',#1350,#585,#1348,.T.);
#1352=ORIENTED_EDGE('',*,*,#1351,.F.);
#1353=CARTESIAN_POINT('',(0.825,0.,0.));
#1354=DIRECTION('',(-1.,0.,0.));
#1355=DIRECTION('',(0.,-1.,0.));
#1356=AXIS2_PLACEMENT_3D('',#1353,#1354,#1355);
#1357=CIRCLE('',#1356,3.);
#1358=CARTESIAN_POINT('',(0.825,-0.391578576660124,-2.97433458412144));
#1359=VERTEX_POINT('',#1358);
#1360=EDGE_CURVE('E764',#1359,#1350,#1357,.T.);
#1361=ORIENTED_EDGE('',*,*,#1360,.F.);
#1362=DIRECTION('',(1.,0.,0.));
#1363=VECTOR('',#1362,1.);
#1364=CARTESIAN_POINT('',(0.825,-0.391578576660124,-2.97433458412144));
#1365=LINE('',#1364,#1363);
#1366=EDGE_CURVE('E759',#1359,#598,#1365,.T.);
#1367=ORIENTED_EDGE('',*,*,#1366,.T.);
#1368=ORIENTED_EDGE('',*,*,#610,.F.);
#1369=DIRECTION('',(1.,0.,0.));
#1370=VECTOR('',#1369,1.);
#1371=CARTESIAN_POINT('',(0.825,0.391578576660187,-2.97433458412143));
#1372=LINE('',#1371,#1370);
#1373=CARTESIAN_POINT('',(0.825,0.391578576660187,-2.97433458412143));
#1374=VERTEX_POINT('',#1373);
#1375=EDGE_CURVE('E792',#1374,#607,#1372,.T.);
#1376=ORIENTED_EDGE('',*,*,#1375,.F.);
#1377=CARTESIAN_POINT('',(0.825,0.,0.));
#1378=DIRECTION('',(-1.,0.,0.));
#1379=DIRECTION('',(0.,-0.866025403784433,-0.50000000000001));
#1380=AXIS2_PLACEMENT_3D('',#1377,#1378,#1379);
#1381=CIRCLE('',#1380,3.);
#1382=CARTESIAN_POINT('',(0.825,1.1480502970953,-2.77163859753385));
#1383=VERTEX_POINT('',#1382);
#1384=EDGE_CURVE('E785',#1383,#1374,#1381,.T.);
#1385=ORIENTED_EDGE('',*,*,#1384,.F.);
#1386=DIRECTION('',(1.,0.,0.));
#1387=VECTOR('',#1386,1.);
#1388=CARTESIAN_POINT('',(0.825,1.1480502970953,-2.77163859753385));
#1389=LINE('',#1388,#1387);
#1390=EDGE_CURVE('E777',#1383,#620,#1389,.T.);
#1391=ORIENTED_EDGE('',*,*,#1390,.T.);
#1392=ORIENTED_EDGE('',*,*,#632,.F.);
#1393=DIRECTION('',(1.,0.,0.));
#1394=VECTOR('',#1393,1.);
#1395=CARTESIAN_POINT('',(0.825,1.82628428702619,-2.38006002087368));
#1396=LINE('',#1395,#1394);
#1397=CARTESIAN_POINT('',(0.825,1.82628428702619,-2.38006002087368));
#1398=VERTEX_POINT('',#1397);
#1399=EDGE_CURVE('E809',#1398,#629,#1396,.T.);
#1400=ORIENTED_EDGE('',*,*,#1399,.F.);
#1401=CARTESIAN_POINT('',(0.825,0.,0.));
#1402=DIRECTION('',(-1.,0.,0.));
#1403=DIRECTION('',(0.,-0.499999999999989,-0.866025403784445));
#1404=AXIS2_PLACEMENT_3D('',#1401,#1402,#1403);
#1405=CIRCLE('',#1404,3.);
#1406=CARTESIAN_POINT('',(0.825,2.38006002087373,-1.82628428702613));
#1407=VERTEX_POINT('',#1406);
#1408=EDGE_CURVE('E798',#1407,#1398,#1405,.T.);
#1409=ORIENTED_EDGE('',*,*,#1408,.F.);
#1410=DIRECTION('',(1.,0.,0.));
#1411=VECTOR('',#1410,1.);
#1412=CARTESIAN_POINT('',(0.825,2.38006002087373,-1.82628428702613));
#1413=LINE('',#1412,#1411);
#1414=EDGE_CURVE('E794',#1407,#644,#1413,.T.);
#1415=ORIENTED_EDGE('',*,*,#1414,.T.);
#1416=EDGE_LOOP('',(#1128,#1136,#1145,#1151,#1152,#1160,#1169,#1175,#1176,#1184,#1193,#1199,
#1200,#1208,#1217,#1223,#1224,#1232,#1241,#1247,#1248,#1256,#1265,#1271,#1272,#1280,#1289,#1295,
#1296,#1304,#1313,#1319,#1320,#1328,#1337,#1343,#1344,#1352,#1361,#1367,#1368,#1376,#1385,#1391,
#1392,#1400,#1409,#1415));
#1417=FACE_BOUND('',#1416,.T.);
#1418=ADVANCED_FACE('F939',(#1127,#1417),#1116,.T.);
#1419=CARTESIAN_POINT('',(15.7455,0.,0.));
#1420=DIRECTION('',(-1.,0.,0.));
#1421=DIRECTION('',(0.,0.,1.));
#1422=AXIS2_PLACEMENT_3D('',#1419,#1420,#1421);
#1423=CONICAL_SURFACE('',#1422,2.4095,0.206024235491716);
#1424=ORIENTED_EDGE('',*,*,#1124,.F.);
#1425=EDGE_LOOP('',(#1424));
#1426=FACE_BOUND('',#1425,.T.);
#1427=CARTESIAN_POINT('',(15.7455,0.,0.));
#1428=DIRECTION('',(-1.,0.,0.));
#1429=DIRECTION('',(0.,0.,1.));
#1430=AXIS2_PLACEMENT_3D('',#1427,#1428,#1429);
#1431=CIRCLE('',#1430,2.4095);
#1432=CARTESIAN_POINT('',(15.7455,0.,2.4095));
#1433=VERTEX_POINT('',#1432);
#1434=EDGE_CURVE('E1265',#1433,#1433,#1431,.T.);
#1435=ORIENTED_EDGE('',*,*,#1434,.T.);
#1436=EDGE_LOOP('',(#1435));
#1437=FACE_BOUND('',#1436,.T.);
#1438=ADVANCED_FACE('F933',(#1426,#1437),#1423,.T.);
#1439=CARTESIAN_POINT('',(15.7455,0.,0.));
#1440=DIRECTION('',(-1.,0.,0.));
#1441=DIRECTION('',(0.,0.,1.));
#1442=AXIS2_PLACEMENT_3D('',#1439,#1440,#1441);
#1443=CONICAL_SURFACE('',#1442,2.4095,0.785398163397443);
#1444=CARTESIAN_POINT('',(15.97,0.,0.));
#1445=DIRECTION('',(-1.,0.,0.));
#1446=DIRECTION('',(0.,0.,1.));
#1447=AXIS2_PLACEMENT_3D('',#1444,#1445,#1446);
#1448=CIRCLE('',#1447,2.185);
#1449=CARTESIAN_POINT('',(15.97,0.,2.185));
#1450=VERTEX_POINT('',#1449);
#1451=EDGE_CURVE('E1263',#1450,#1450,#1448,.T.);
#1452=ORIENTED_EDGE('',*,*,#1451,.T.);
#1453=EDGE_LOOP('',(#1452));
#1454=FACE_BOUND('',#1453,.T.);
#1455=ORIENTED_EDGE('',*,*,#1434,.F.);
#1456=EDGE_LOOP('',(#1455));
#1457=FACE_BOUND('',#1456,.T.);
#1458=ADVANCED_FACE('F930',(#1454,#1457),#1443,.T.);
#1459=CARTESIAN_POINT('',(0.,0.,0.));
#1460=DIRECTION('',(-1.,0.,0.));
#1461=DIRECTION('',(0.,0.,1.));
#1462=AXIS2_PLACEMENT_3D('',#1459,#1460,#1461);
#1463=CYLINDRICAL_SURFACE('',#1462,2.185);
#1464=CARTESIAN_POINT('',(18.,0.,0.));
#1465=DIRECTION('',(-1.,0.,0.));
#1466=DIRECTION('',(0.,0.,1.));
#1467=AXIS2_PLACEMENT_3D('',#1464,#1465,#1466);
#1468=CIRCLE('',#1467,2.185);
#1469=CARTESIAN_POINT('',(18.,0.,2.185));
#1470=VERTEX_POINT('',#1469);
#1471=EDGE_CURVE('E1270',#1470,#1470,#1468,.T.);
#1472=ORIENTED_EDGE('',*,*,#1471,.T.);
#1473=EDGE_LOOP('',(#1472));
#1474=FACE_BOUND('',#1473,.T.);
#1475=ORIENTED_EDGE('',*,*,#1451,.F.);
#1476=EDGE_LOOP('',(#1475));
#1477=FACE_BOUND('',#1476,.T.);
#1478=ADVANCED_FACE('F926',(#1474,#1477),#1463,.T.);
#1479=CARTESIAN_POINT('',(18.,2.185,0.));
#1480=DIRECTION('',(1.,0.,0.));
#1481=DIRECTION('',(0.,0.,-1.));
#1482=AXIS2_PLACEMENT_3D('',#1479,#1480,#1481);
#1483=PLANE('',#1482);
#1484=ORIENTED_EDGE('',*,*,#1471,.F.);
#1485=EDGE_LOOP('',(#1484));
#1486=FACE_BOUND('',#1485,.T.);
#1487=ADVANCED_FACE('F921',(#1486),#1483,.T.);
#1488=CARTESIAN_POINT('',(0.825,2.97433458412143,-0.391578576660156));
#1489=DIRECTION('',(0.,0.,1.));
#1490=DIRECTION('',(1.,0.,0.));
#1491=AXIS2_PLACEMENT_3D('',#1488,#1489,#1490);
#1492=PLANE('',#1491);
#1493=DIRECTION('',(0.,-1.,0.));
#1494=VECTOR('',#1493,1.);
#1495=CARTESIAN_POINT('',(0.825,2.97433458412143,-0.391578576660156));
#1496=LINE('',#1495,#1494);
#1497=CARTESIAN_POINT('',(0.825,3.34465580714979,-0.391578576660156));
#1498=VERTEX_POINT('',#1497);
#1499=EDGE_CURVE('E889',#1498,#1143,#1496,.T.);
#1500=ORIENTED_EDGE('',*,*,#1499,.F.);
#1501=DIRECTION('',(1.,0.,0.));
#1502=VECTOR('',#1501,1.);
#1503=CARTESIAN_POINT('',(0.6,3.34465580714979,-0.391578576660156));
#1504=LINE('',#1503,#1502);
#1505=EDGE_CURVE('E877',#1017,#1498,#1504,.T.);
#1506=ORIENTED_EDGE('',*,*,#1505,.F.);
#1507=ORIENTED_EDGE('',*,*,#1018,.F.);
#1508=ORIENTED_EDGE('',*,*,#424,.T.);
#1509=ORIENTED_EDGE('',*,*,#1106,.T.);
#1510=ORIENTED_EDGE('',*,*,#1150,.F.);
#1511=EDGE_LOOP('',(#1500,#1506,#1507,#1508,#1509,#1510));
#1512=FACE_BOUND('',#1511,.T.);
#1513=ADVANCED_FACE('F916',(#1512),#1492,.F.);
#1514=CARTESIAN_POINT('',(0.825,2.77163859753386,-1.14805029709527));
#1515=DIRECTION('',(0.,-0.500000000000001,-0.866025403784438));
#1516=DIRECTION('',(0.,0.866025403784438,-0.500000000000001));
#1517=AXIS2_PLACEMENT_3D('',#1514,#1515,#1516);
#1518=PLANE('',#1517);
#1519=ORIENTED_EDGE('',*,*,#657,.T.);
#1520=ORIENTED_EDGE('',*,*,#1084,.T.);
#1521=ORIENTED_EDGE('',*,*,#1035,.F.);
#1522=DIRECTION('',(1.,0.,0.));
#1523=VECTOR('',#1522,1.);
#1524=CARTESIAN_POINT('',(0.6,3.09234618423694,-1.33321090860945));
#1525=LINE('',#1524,#1523);
#1526=CARTESIAN_POINT('',(0.825,3.09234618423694,-1.33321090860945));
#1527=VERTEX_POINT('',#1526);
#1528=EDGE_CURVE('E876',#1026,#1527,#1525,.T.);
#1529=ORIENTED_EDGE('',*,*,#1528,.T.);
#1530=DIRECTION('',(0.,0.866025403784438,-0.500000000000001));
#1531=VECTOR('',#1530,1.);
#1532=CARTESIAN_POINT('',(0.825,2.77163859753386,-1.14805029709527));
#1533=LINE('',#1532,#1531);
#1534=EDGE_CURVE('E886',#1134,#1527,#1533,.T.);
#1535=ORIENTED_EDGE('',*,*,#1534,.F.);
#1536=ORIENTED_EDGE('',*,*,#1135,.T.);
#1537=EDGE_LOOP('',(#1519,#1520,#1521,#1529,#1535,#1536));
#1538=FACE_BOUND('',#1537,.T.);
#1539=ADVANCED_FACE('F913',(#1538),#1518,.F.);
#1540=CARTESIAN_POINT('',(0.825,0.,0.));
#1541=DIRECTION('',(1.,0.,0.));
#1542=DIRECTION('',(0.,0.,-1.));
#1543=AXIS2_PLACEMENT_3D('',#1540,#1541,#1542);
#1544=PLANE('',#1543);
#1545=CARTESIAN_POINT('',(0.825,0.,0.));
#1546=DIRECTION('',(1.,0.,0.));
#1547=DIRECTION('',(0.,0.,-1.));
#1548=AXIS2_PLACEMENT_3D('',#1545,#1546,#1547);
#1549=CIRCLE('',#1548,3.3675);
#1550=EDGE_CURVE('E1289',#1498,#1527,#1549,.F.);
#1551=ORIENTED_EDGE('',*,*,#1550,.F.);
#1552=ORIENTED_EDGE('',*,*,#1499,.T.);
#1553=ORIENTED_EDGE('',*,*,#1144,.T.);
#1554=ORIENTED_EDGE('',*,*,#1534,.T.);
#1555=EDGE_LOOP('',(#1551,#1552,#1553,#1554));
#1556=FACE_BOUND('',#1555,.T.);
#1557=ADVANCED_FACE('F919',(#1556),#1544,.T.);
#1558=CARTESIAN_POINT('',(0.6,0.,0.));
#1559=DIRECTION('',(1.,0.,0.));
#1560=DIRECTION('',(0.,0.,-1.));
#1561=AXIS2_PLACEMENT_3D('',#1558,#1559,#1560);
#1562=CYLINDRICAL_SURFACE('',#1561,3.3675);
#1563=ORIENTED_EDGE('',*,*,#1550,.T.);
#1564=ORIENTED_EDGE('',*,*,#1528,.F.);
#1565=ORIENTED_EDGE('',*,*,#1027,.F.);
#1566=ORIENTED_EDGE('',*,*,#1505,.T.);
#1567=EDGE_LOOP('',(#1563,#1564,#1565,#1566));
#1568=FACE_BOUND('',#1567,.T.);
#1569=ADVANCED_FACE('F849',(#1568),#1562,.T.);
#1570=CARTESIAN_POINT('',(0.825,2.77163859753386,1.14805029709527));
#1571=DIRECTION('',(0.,-0.500000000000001,0.866025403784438));
#1572=DIRECTION('',(0.,-0.866025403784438,-0.500000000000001));
#1573=AXIS2_PLACEMENT_3D('',#1570,#1571,#1572);
#1574=PLANE('',#1573);
#1575=DIRECTION('',(0.,-0.866025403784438,-0.500000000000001));
#1576=VECTOR('',#1575,1.);
#1577=CARTESIAN_POINT('',(0.825,2.77163859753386,1.14805029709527));
#1578=LINE('',#1577,#1576);
#1579=CARTESIAN_POINT('',(0.825,3.09234618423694,1.33321090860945));
#1580=VERTEX_POINT('',#1579);
#1581=EDGE_CURVE('E1542',#1580,#1167,#1578,.T.);
#1582=ORIENTED_EDGE('',*,*,#1581,.F.);
#1583=DIRECTION('',(1.,0.,0.));
#1584=VECTOR('',#1583,1.);
#1585=CARTESIAN_POINT('',(0.6,3.09234618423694,1.33321090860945));
#1586=LINE('',#1585,#1584);
#1587=EDGE_CURVE('E644',#993,#1580,#1586,.T.);
#1588=ORIENTED_EDGE('',*,*,#1587,.F.);
#1589=ORIENTED_EDGE('',*,*,#994,.F.);
#1590=ORIENTED_EDGE('',*,*,#62,.T.);
#1591=ORIENTED_EDGE('',*,*,#680,.T.);
#1592=ORIENTED_EDGE('',*,*,#1174,.F.);
#1593=EDGE_LOOP('',(#1582,#1588,#1589,#1590,#1591,#1592));
#1594=FACE_BOUND('',#1593,.T.);
#1595=ADVANCED_FACE('F846',(#1594),#1574,.F.);
#1596=CARTESIAN_POINT('',(0.825,2.97433458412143,0.391578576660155));
#1597=DIRECTION('',(0.,0.,-1.));
#1598=DIRECTION('',(-1.,0.,0.));
#1599=AXIS2_PLACEMENT_3D('',#1596,#1597,#1598);
#1600=PLANE('',#1599);
#1601=ORIENTED_EDGE('',*,*,#1096,.T.);
#1602=ORIENTED_EDGE('',*,*,#407,.T.);
#1603=ORIENTED_EDGE('',*,*,#1009,.F.);
#1604=DIRECTION('',(1.,0.,0.));
#1605=VECTOR('',#1604,1.);
#1606=CARTESIAN_POINT('',(0.6,3.34465580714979,0.391578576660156));
#1607=LINE('',#1606,#1605);
#1608=CARTESIAN_POINT('',(0.825,3.34465580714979,0.391578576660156));
#1609=VERTEX_POINT('',#1608);
#1610=EDGE_CURVE('E641',#1002,#1609,#1607,.T.);
#1611=ORIENTED_EDGE('',*,*,#1610,.T.);
#1612=DIRECTION('',(0.,1.,0.));
#1613=VECTOR('',#1612,1.);
#1614=CARTESIAN_POINT('',(0.825,2.97433458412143,0.391578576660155));
#1615=LINE('',#1614,#1613);
#1616=EDGE_CURVE('E1545',#1158,#1609,#1615,.T.);
#1617=ORIENTED_EDGE('',*,*,#1616,.F.);
#1618=ORIENTED_EDGE('',*,*,#1159,.T.);
#1619=EDGE_LOOP('',(#1601,#1602,#1603,#1611,#1617,#1618));
#1620=FACE_BOUND('',#1619,.T.);
#1621=ADVANCED_FACE('F843',(#1620),#1600,.F.);
#1622=CARTESIAN_POINT('',(0.825,0.,0.));
#1623=DIRECTION('',(1.,0.,0.));
#1624=DIRECTION('',(0.,0.500000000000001,-0.866025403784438));
#1625=AXIS2_PLACEMENT_3D('',#1622,#1623,#1624);
#1626=PLANE('',#1625);
#1627=CARTESIAN_POINT('',(0.825,0.,0.));
#1628=DIRECTION('',(1.,0.,0.));
#1629=DIRECTION('',(0.,0.,-1.));
#1630=AXIS2_PLACEMENT_3D('',#1627,#1628,#1629);
#1631=CIRCLE('',#1630,3.3675);
#1632=EDGE_CURVE('E1294',#1580,#1609,#1631,.F.);
#1633=ORIENTED_EDGE('',*,*,#1632,.F.);
#1634=ORIENTED_EDGE('',*,*,#1581,.T.);
#1635=ORIENTED_EDGE('',*,*,#1168,.T.);
#1636=ORIENTED_EDGE('',*,*,#1616,.T.);
#1637=EDGE_LOOP('',(#1633,#1634,#1635,#1636));
#1638=FACE_BOUND('',#1637,.T.);
#1639=ADVANCED_FACE('F841',(#1638),#1626,.T.);
#1640=CARTESIAN_POINT('',(0.825,2.38006002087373,-1.82628428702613));
#1641=DIRECTION('',(0.,0.499999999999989,0.866025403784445));
#1642=DIRECTION('',(0.,-0.866025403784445,0.499999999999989));
#1643=AXIS2_PLACEMENT_3D('',#1640,#1641,#1642);
#1644=PLANE('',#1643);
#1645=DIRECTION('',(0.,-0.866025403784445,0.499999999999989));
#1646=VECTOR('',#1645,1.);
#1647=CARTESIAN_POINT('',(0.825,2.38006002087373,-1.82628428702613));
#1648=LINE('',#1647,#1646);
#1649=CARTESIAN_POINT('',(0.825,2.70076760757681,-2.01144489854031));
#1650=VERTEX_POINT('',#1649);
#1651=EDGE_CURVE('E807',#1650,#1407,#1648,.T.);
#1652=ORIENTED_EDGE('',*,*,#1651,.F.);
#1653=DIRECTION('',(1.,0.,0.));
#1654=VECTOR('',#1653,1.);
#1655=CARTESIAN_POINT('',(0.6,2.70076760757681,-2.01144489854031));
#1656=LINE('',#1655,#1654);
#1657=EDGE_CURVE('E635',#1046,#1650,#1656,.T.);
#1658=ORIENTED_EDGE('',*,*,#1657,.F.);
#1659=ORIENTED_EDGE('',*,*,#1047,.F.);
#1660=ORIENTED_EDGE('',*,*,#1074,.T.);
#1661=ORIENTED_EDGE('',*,*,#645,.T.);
#1662=ORIENTED_EDGE('',*,*,#1414,.F.);
#1663=EDGE_LOOP('',(#1652,#1658,#1659,#1660,#1661,#1662));
#1664=FACE_BOUND('',#1663,.T.);
#1665=ADVANCED_FACE('F840',(#1664),#1644,.F.);
#1666=CARTESIAN_POINT('',(0.825,1.82628428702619,-2.38006002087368));
#1667=DIRECTION('',(0.,-0.866025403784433,-0.50000000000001));
#1668=DIRECTION('',(0.,0.50000000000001,-0.866025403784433));
#1669=AXIS2_PLACEMENT_3D('',#1666,#1667,#1668);
#1670=PLANE('',#1669);
#1671=ORIENTED_EDGE('',*,*,#630,.T.);
#1672=ORIENTED_EDGE('',*,*,#381,.T.);
#1673=ORIENTED_EDGE('',*,*,#1062,.F.);
#1674=DIRECTION('',(1.,0.,0.));
#1675=VECTOR('',#1674,1.);
#1676=CARTESIAN_POINT('',(0.6,2.01144489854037,-2.70076760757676));
#1677=LINE('',#1676,#1675);
#1678=CARTESIAN_POINT('',(0.825,2.01144489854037,-2.70076760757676));
#1679=VERTEX_POINT('',#1678);
#1680=EDGE_CURVE('E611',#1055,#1679,#1677,.T.);
#1681=ORIENTED_EDGE('',*,*,#1680,.T.);
#1682=DIRECTION('',(0.,0.50000000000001,-0.866025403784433));
#1683=VECTOR('',#1682,1.);
#1684=CARTESIAN_POINT('',(0.825,1.82628428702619,-2.38006002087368));
#1685=LINE('',#1684,#1683);
#1686=EDGE_CURVE('E805',#1398,#1679,#1685,.T.);
#1687=ORIENTED_EDGE('',*,*,#1686,.F.);
#1688=ORIENTED_EDGE('',*,*,#1399,.T.);
#1689=EDGE_LOOP('',(#1671,#1672,#1673,#1681,#1687,#1688));
#1690=FACE_BOUND('',#1689,.T.);
#1691=ADVANCED_FACE('F835',(#1690),#1670,.F.);
#1692=CARTESIAN_POINT('',(0.825,0.,0.));
#1693=DIRECTION('',(1.,0.,0.));
#1694=DIRECTION('',(0.,-0.499999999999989,-0.866025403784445));
#1695=AXIS2_PLACEMENT_3D('',#1692,#1693,#1694);
#1696=PLANE('',#1695);
#1697=CARTESIAN_POINT('',(0.825,0.,0.));
#1698=DIRECTION('',(1.,0.,0.));
#1699=DIRECTION('',(0.,0.,-1.));
#1700=AXIS2_PLACEMENT_3D('',#1697,#1698,#1699);
#1701=CIRCLE('',#1700,3.3675);
#1702=EDGE_CURVE('E11',#1650,#1679,#1701,.F.);
#1703=ORIENTED_EDGE('',*,*,#1702,.F.);
#1704=ORIENTED_EDGE('',*,*,#1651,.T.);
#1705=ORIENTED_EDGE('',*,*,#1408,.T.);
#1706=ORIENTED_EDGE('',*,*,#1686,.T.);
#1707=EDGE_LOOP('',(#1703,#1704,#1705,#1706));
#1708=FACE_BOUND('',#1707,.T.);
#1709=ADVANCED_FACE('F837',(#1708),#1696,.T.);
#1710=CARTESIAN_POINT('',(0.825,1.1480502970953,-2.77163859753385));
#1711=DIRECTION('',(0.,0.866025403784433,0.50000000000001));
#1712=DIRECTION('',(0.,-0.50000000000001,0.866025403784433));
#1713=AXIS2_PLACEMENT_3D('',#1710,#1711,#1712);
#1714=PLANE('',#1713);
#1715=DIRECTION('',(0.,-0.50000000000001,0.866025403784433));
#1716=VECTOR('',#1715,1.);
#1717=CARTESIAN_POINT('',(0.825,1.1480502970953,-2.77163859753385));
#1718=LINE('',#1717,#1716);
#1719=CARTESIAN_POINT('',(0.825,1.33321090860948,-3.09234618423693));
#1720=VERTEX_POINT('',#1719);
#1721=EDGE_CURVE('E786',#1720,#1383,#1718,.T.);
#1722=ORIENTED_EDGE('',*,*,#1721,.F.);
#1723=DIRECTION('',(1.,0.,0.));
#1724=VECTOR('',#1723,1.);
#1725=CARTESIAN_POINT('',(0.6,1.33321090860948,-3.09234618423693));
#1726=LINE('',#1725,#1724);
#1727=EDGE_CURVE('E619',#777,#1720,#1726,.T.);
#1728=ORIENTED_EDGE('',*,*,#1727,.F.);
#1729=ORIENTED_EDGE('',*,*,#778,.F.);
#1730=ORIENTED_EDGE('',*,*,#366,.T.);
#1731=ORIENTED_EDGE('',*,*,#621,.T.);
#1732=ORIENTED_EDGE('',*,*,#1390,.F.);
#1733=EDGE_LOOP('',(#1722,#1728,#1729,#1730,#1731,#1732));
#1734=FACE_BOUND('',#1733,.T.);
#1735=ADVANCED_FACE('F1208',(#1734),#1714,.F.);
#1736=CARTESIAN_POINT('',(0.825,0.391578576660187,-2.97433458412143));
#1737=DIRECTION('',(0.,-1.,0.));
#1738=DIRECTION('',(0.,0.,-1.));
#1739=AXIS2_PLACEMENT_3D('',#1736,#1737,#1738);
#1740=PLANE('',#1739);
#1741=ORIENTED_EDGE('',*,*,#608,.T.);
#1742=ORIENTED_EDGE('',*,*,#348,.T.);
#1743=ORIENTED_EDGE('',*,*,#793,.F.);
#1744=DIRECTION('',(1.,0.,0.));
#1745=VECTOR('',#1744,1.);
#1746=CARTESIAN_POINT('',(0.6,0.391578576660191,-3.34465580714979));
#1747=LINE('',#1746,#1745);
#1748=CARTESIAN_POINT('',(0.825,0.391578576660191,-3.34465580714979));
#1749=VERTEX_POINT('',#1748);
#1750=EDGE_CURVE('E601',#786,#1749,#1747,.T.);
#1751=ORIENTED_EDGE('',*,*,#1750,.T.);
#1752=DIRECTION('',(0.,0.,-1.));
#1753=VECTOR('',#1752,1.);
#1754=CARTESIAN_POINT('',(0.825,0.391578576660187,-2.97433458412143));
#1755=LINE('',#1754,#1753);
#1756=EDGE_CURVE('E784',#1374,#1749,#1755,.T.);
#1757=ORIENTED_EDGE('',*,*,#1756,.F.);
#1758=ORIENTED_EDGE('',*,*,#1375,.T.);
#1759=EDGE_LOOP('',(#1741,#1742,#1743,#1751,#1757,#1758));
#1760=FACE_BOUND('',#1759,.T.);
#1761=ADVANCED_FACE('F1205',(#1760),#1740,.F.);
#1762=CARTESIAN_POINT('',(0.825,0.,0.));
#1763=DIRECTION('',(1.,0.,0.));
#1764=DIRECTION('',(0.,-0.866025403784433,-0.50000000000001));
#1765=AXIS2_PLACEMENT_3D('',#1762,#1763,#1764);
#1766=PLANE('',#1765);
#1767=CARTESIAN_POINT('',(0.825,0.,0.));
#1768=DIRECTION('',(1.,0.,0.));
#1769=DIRECTION('',(0.,0.,-1.));
#1770=AXIS2_PLACEMENT_3D('',#1767,#1768,#1769);
#1771=CIRCLE('',#1770,3.3675);
#1772=EDGE_CURVE('E50',#1720,#1749,#1771,.F.);
#1773=ORIENTED_EDGE('',*,*,#1772,.F.);
#1774=ORIENTED_EDGE('',*,*,#1721,.T.);
#1775=ORIENTED_EDGE('',*,*,#1384,.T.);
#1776=ORIENTED_EDGE('',*,*,#1756,.T.);
#1777=EDGE_LOOP('',(#1773,#1774,#1775,#1776));
#1778=FACE_BOUND('',#1777,.T.);
#1779=ADVANCED_FACE('F1197',(#1778),#1766,.T.);
#1780=CARTESIAN_POINT('',(0.825,-0.391578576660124,-2.97433458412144));
#1781=DIRECTION('',(0.,1.,0.));
#1782=DIRECTION('',(0.,0.,1.));
#1783=AXIS2_PLACEMENT_3D('',#1780,#1781,#1782);
#1784=PLANE('',#1783);
#1785=DIRECTION('',(0.,0.,1.));
#1786=VECTOR('',#1785,1.);
#1787=CARTESIAN_POINT('',(0.825,-0.391578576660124,-2.97433458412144));
#1788=LINE('',#1787,#1786);
#1789=CARTESIAN_POINT('',(0.825,-0.391578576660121,-3.34465580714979));
#1790=VERTEX_POINT('',#1789);
#1791=EDGE_CURVE('E775',#1790,#1359,#1788,.T.);
#1792=ORIENTED_EDGE('',*,*,#1791,.F.);
#1793=DIRECTION('',(1.,0.,0.));
#1794=VECTOR('',#1793,1.);
#1795=CARTESIAN_POINT('',(0.6,-0.391578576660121,-3.34465580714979));
#1796=LINE('',#1795,#1794);
#1797=EDGE_CURVE('E610',#801,#1790,#1796,.T.);
#1798=ORIENTED_EDGE('',*,*,#1797,.F.);
#1799=ORIENTED_EDGE('',*,*,#802,.F.);
#1800=ORIENTED_EDGE('',*,*,#329,.T.);
#1801=ORIENTED_EDGE('',*,*,#599,.T.);
#1802=ORIENTED_EDGE('',*,*,#1366,.F.);
#1803=EDGE_LOOP('',(#1792,#1798,#1799,#1800,#1801,#1802));
#1804=FACE_BOUND('',#1803,.T.);
#1805=ADVANCED_FACE('F1195',(#1804),#1784,.F.);
#1806=CARTESIAN_POINT('',(0.825,-1.14805029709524,-2.77163859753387));
#1807=DIRECTION('',(0.,-0.866025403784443,0.499999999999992));
#1808=DIRECTION('',(0.,-0.499999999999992,-0.866025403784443));
#1809=AXIS2_PLACEMENT_3D('',#1806,#1807,#1808);
#1810=PLANE('',#1809);
#1811=ORIENTED_EDGE('',*,*,#586,.T.);
#1812=ORIENTED_EDGE('',*,*,#307,.T.);
#1813=ORIENTED_EDGE('',*,*,#817,.F.);
#1814=DIRECTION('',(1.,0.,0.));
#1815=VECTOR('',#1814,1.);
#1816=CARTESIAN_POINT('',(0.6,-1.33321090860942,-3.09234618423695));
#1817=LINE('',#1816,#1815);
#1818=CARTESIAN_POINT('',(0.825,-1.33321090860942,-3.09234618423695));
#1819=VERTEX_POINT('',#1818);
#1820=EDGE_CURVE('E587',#810,#1819,#1817,.T.);
#1821=ORIENTED_EDGE('',*,*,#1820,.T.);
#1822=DIRECTION('',(0.,-0.499999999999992,-0.866025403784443));
#1823=VECTOR('',#1822,1.);
#1824=CARTESIAN_POINT('',(0.825,-1.14805029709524,-2.77163859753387));
#1825=LINE('',#1824,#1823);
#1826=EDGE_CURVE('E767',#1350,#1819,#1825,.T.);
#1827=ORIENTED_EDGE('',*,*,#1826,.F.);
#1828=ORIENTED_EDGE('',*,*,#1351,.T.);
#1829=EDGE_LOOP('',(#1811,#1812,#1813,#1821,#1827,#1828));
#1830=FACE_BOUND('',#1829,.T.);
#1831=ADVANCED_FACE('F1194',(#1830),#1810,.F.);
#1832=CARTESIAN_POINT('',(0.825,0.,0.));
#1833=DIRECTION('',(1.,0.,0.));
#1834=DIRECTION('',(0.,-1.,0.));
#1835=AXIS2_PLACEMENT_3D('',#1832,#1833,#1834);
#1836=PLANE('',#1835);
#1837=CARTESIAN_POINT('',(0.825,0.,0.));
#1838=DIRECTION('',(1.,0.,0.));
#1839=DIRECTION('',(0.,0.,-1.));
#1840=AXIS2_PLACEMENT_3D('',#1837,#1838,#1839);
#1841=CIRCLE('',#1840,3.3675);
#1842=EDGE_CURVE('E1316',#1790,#1819,#1841,.F.);
#1843=ORIENTED_EDGE('',*,*,#1842,.F.);
#1844=ORIENTED_EDGE('',*,*,#1791,.T.);
#1845=ORIENTED_EDGE('',*,*,#1360,.T.);
#1846=ORIENTED_EDGE('',*,*,#1826,.T.);
#1847=EDGE_LOOP('',(#1843,#1844,#1845,#1846));
#1848=FACE_BOUND('',#1847,.T.);
#1849=ADVANCED_FACE('F1165',(#1848),#1836,.T.);
#1850=CARTESIAN_POINT('',(0.825,-1.82628428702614,-2.38006002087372));
#1851=DIRECTION('',(0.,0.866025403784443,-0.499999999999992));
#1852=DIRECTION('',(0.,0.499999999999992,0.866025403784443));
#1853=AXIS2_PLACEMENT_3D('',#1850,#1851,#1852);
#1854=PLANE('',#1853);
#1855=DIRECTION('',(0.,0.499999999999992,0.866025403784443));
#1856=VECTOR('',#1855,1.);
#1857=CARTESIAN_POINT('',(0.825,-1.82628428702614,-2.38006002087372));
#1858=LINE('',#1857,#1856);
#1859=CARTESIAN_POINT('',(0.825,-2.01144489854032,-2.7007676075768));
#1860=VERTEX_POINT('',#1859);
#1861=EDGE_CURVE('E752',#1860,#1335,#1858,.T.);
#1862=ORIENTED_EDGE('',*,*,#1861,.F.);
#1863=DIRECTION('',(1.,0.,0.));
#1864=VECTOR('',#1863,1.);
#1865=CARTESIAN_POINT('',(0.6,-2.01144489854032,-2.7007676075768));
#1866=LINE('',#1865,#1864);
#1867=EDGE_CURVE('E591',#825,#1860,#1866,.T.);
#1868=ORIENTED_EDGE('',*,*,#1867,.F.);
#1869=ORIENTED_EDGE('',*,*,#826,.F.);
#1870=ORIENTED_EDGE('',*,*,#292,.T.);
#1871=ORIENTED_EDGE('',*,*,#577,.T.);
#1872=ORIENTED_EDGE('',*,*,#1342,.F.);
#1873=EDGE_LOOP('',(#1862,#1868,#1869,#1870,#1871,#1872));
#1874=FACE_BOUND('',#1873,.T.);
#1875=ADVANCED_FACE('F1157',(#1874),#1854,.F.);
#1876=CARTESIAN_POINT('',(0.825,-2.38006002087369,-1.82628428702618));
#1877=DIRECTION('',(0.,-0.500000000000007,0.866025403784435));
#1878=DIRECTION('',(0.,-0.866025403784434,-0.500000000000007));
#1879=AXIS2_PLACEMENT_3D('',#1876,#1877,#1878);
#1880=PLANE('',#1879);
#1881=ORIENTED_EDGE('',*,*,#564,.T.);
#1882=ORIENTED_EDGE('',*,*,#274,.T.);
#1883=ORIENTED_EDGE('',*,*,#841,.F.);
#1884=DIRECTION('',(1.,0.,0.));
#1885=VECTOR('',#1884,1.);
#1886=CARTESIAN_POINT('',(0.6,-2.70076760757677,-2.01144489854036));
#1887=LINE('',#1886,#1885);
#1888=CARTESIAN_POINT('',(0.825,-2.70076760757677,-2.01144489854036));
#1889=VERTEX_POINT('',#1888);
#1890=EDGE_CURVE('E574',#834,#1889,#1887,.T.);
#1891=ORIENTED_EDGE('',*,*,#1890,.T.);
#1892=DIRECTION('',(0.,-0.866025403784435,-0.500000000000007));
#1893=VECTOR('',#1892,1.);
#1894=CARTESIAN_POINT('',(0.825,-2.38006002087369,-1.82628428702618));
#1895=LINE('',#1894,#1893);
#1896=EDGE_CURVE('E753',#1326,#1889,#1895,.T.);
#1897=ORIENTED_EDGE('',*,*,#1896,.F.);
#1898=ORIENTED_EDGE('',*,*,#1327,.T.);
#1899=EDGE_LOOP('',(#1881,#1882,#1883,#1891,#1897,#1898));
#1900=FACE_BOUND('',#1899,.T.);
#1901=ADVANCED_FACE('F1156',(#1900),#1880,.F.);
#1902=CARTESIAN_POINT('',(0.825,0.,0.));
#1903=DIRECTION('',(1.,0.,0.));
#1904=DIRECTION('',(0.,-0.866025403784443,0.499999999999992));
#1905=AXIS2_PLACEMENT_3D('',#1902,#1903,#1904);
#1906=PLANE('',#1905);
#1907=CARTESIAN_POINT('',(0.825,0.,0.));
#1908=DIRECTION('',(1.,0.,0.));
#1909=DIRECTION('',(0.,0.,-1.));
#1910=AXIS2_PLACEMENT_3D('',#1907,#1908,#1909);
#1911=CIRCLE('',#1910,3.3675);
#1912=EDGE_CURVE('E1314',#1860,#1889,#1911,.F.);
#1913=ORIENTED_EDGE('',*,*,#1912,.F.);
#1914=ORIENTED_EDGE('',*,*,#1861,.T.);
#1915=ORIENTED_EDGE('',*,*,#1336,.T.);
#1916=ORIENTED_EDGE('',*,*,#1896,.T.);
#1917=EDGE_LOOP('',(#1913,#1914,#1915,#1916));
#1918=FACE_BOUND('',#1917,.T.);
#1919=ADVANCED_FACE('F1148',(#1918),#1906,.T.);
#1920=CARTESIAN_POINT('',(0.825,-2.77163859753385,-1.14805029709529));
#1921=DIRECTION('',(0.,0.500000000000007,-0.866025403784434));
#1922=DIRECTION('',(0.,0.866025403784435,0.500000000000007));
#1923=AXIS2_PLACEMENT_3D('',#1920,#1921,#1922);
#1924=PLANE('',#1923);
#1925=DIRECTION('',(0.,0.866025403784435,0.500000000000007));
#1926=VECTOR('',#1925,1.);
#1927=CARTESIAN_POINT('',(0.825,-2.77163859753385,-1.14805029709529));
#1928=LINE('',#1927,#1926);
#1929=CARTESIAN_POINT('',(0.825,-3.09234618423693,-1.33321090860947));
#1930=VERTEX_POINT('',#1929);
#1931=EDGE_CURVE('E737',#1930,#1311,#1928,.T.);
#1932=ORIENTED_EDGE('',*,*,#1931,.F.);
#1933=DIRECTION('',(1.,0.,0.));
#1934=VECTOR('',#1933,1.);
#1935=CARTESIAN_POINT('',(0.6,-3.09234618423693,-1.33321090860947));
#1936=LINE('',#1935,#1934);
#1937=EDGE_CURVE('E581',#849,#1930,#1936,.T.);
#1938=ORIENTED_EDGE('',*,*,#1937,.F.);
#1939=ORIENTED_EDGE('',*,*,#850,.F.);
#1940=ORIENTED_EDGE('',*,*,#259,.T.);
#1941=ORIENTED_EDGE('',*,*,#555,.T.);
#1942=ORIENTED_EDGE('',*,*,#1318,.F.);
#1943=EDGE_LOOP('',(#1932,#1938,#1939,#1940,#1941,#1942));
#1944=FACE_BOUND('',#1943,.T.);
#1945=ADVANCED_FACE('F1144',(#1944),#1924,.F.);
#1946=CARTESIAN_POINT('',(0.825,-2.97433458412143,-0.391578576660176));
#1947=DIRECTION('',(0.,0.,1.));
#1948=DIRECTION('',(0.,-1.,0.));
#1949=AXIS2_PLACEMENT_3D('',#1946,#1947,#1948);
#1950=PLANE('',#1949);
#1951=ORIENTED_EDGE('',*,*,#542,.T.);
#1952=ORIENTED_EDGE('',*,*,#241,.T.);
#1953=ORIENTED_EDGE('',*,*,#865,.F.);
#1954=DIRECTION('',(1.,0.,0.));
#1955=VECTOR('',#1954,1.);
#1956=CARTESIAN_POINT('',(0.6,-3.34465580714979,-0.391578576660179));
#1957=LINE('',#1956,#1955);
#1958=CARTESIAN_POINT('',(0.825,-3.34465580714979,-0.391578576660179));
#1959=VERTEX_POINT('',#1958);
#1960=EDGE_CURVE('E565',#858,#1959,#1957,.T.);
#1961=ORIENTED_EDGE('',*,*,#1960,.T.);
#1962=DIRECTION('',(0.,-1.,0.));
#1963=VECTOR('',#1962,1.);
#1964=CARTESIAN_POINT('',(0.825,-2.97433458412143,-0.391578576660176));
#1965=LINE('',#1964,#1963);
#1966=EDGE_CURVE('E733',#1302,#1959,#1965,.T.);
#1967=ORIENTED_EDGE('',*,*,#1966,.F.);
#1968=ORIENTED_EDGE('',*,*,#1303,.T.);
#1969=EDGE_LOOP('',(#1951,#1952,#1953,#1961,#1967,#1968));
#1970=FACE_BOUND('',#1969,.T.);
#1971=ADVANCED_FACE('F1150',(#1970),#1950,.F.);
#1972=CARTESIAN_POINT('',(0.825,0.,0.));
#1973=DIRECTION('',(1.,0.,0.));
#1974=DIRECTION('',(0.,-0.500000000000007,0.866025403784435));
#1975=AXIS2_PLACEMENT_3D('',#1972,#1973,#1974);
#1976=PLANE('',#1975);
#1977=CARTESIAN_POINT('',(0.825,0.,0.));
#1978=DIRECTION('',(1.,0.,0.));
#1979=DIRECTION('',(0.,0.,-1.));
#1980=AXIS2_PLACEMENT_3D('',#1977,#1978,#1979);
#1981=CIRCLE('',#1980,3.3675);
#1982=EDGE_CURVE('E1315',#1930,#1959,#1981,.F.);
#1983=ORIENTED_EDGE('',*,*,#1982,.F.);
#1984=ORIENTED_EDGE('',*,*,#1931,.T.);
#1985=ORIENTED_EDGE('',*,*,#1312,.T.);
#1986=ORIENTED_EDGE('',*,*,#1966,.T.);
#1987=EDGE_LOOP('',(#1983,#1984,#1985,#1986));
#1988=FACE_BOUND('',#1987,.T.);
#1989=ADVANCED_FACE('F1111',(#1988),#1976,.T.);
#1990=CARTESIAN_POINT('',(0.825,-2.97433458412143,0.391578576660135));
#1991=DIRECTION('',(0.,0.,-1.));
#1992=DIRECTION('',(0.,1.,0.));
#1993=AXIS2_PLACEMENT_3D('',#1990,#1991,#1992);
#1994=PLANE('',#1993);
#1995=DIRECTION('',(0.,1.,0.));
#1996=VECTOR('',#1995,1.);
#1997=CARTESIAN_POINT('',(0.825,-2.97433458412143,0.391578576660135));
#1998=LINE('',#1997,#1996);
#1999=CARTESIAN_POINT('',(0.825,-3.34465580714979,0.391578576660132));
#2000=VERTEX_POINT('',#1999);
#2001=EDGE_CURVE('E722',#2000,#1287,#1998,.T.);
#2002=ORIENTED_EDGE('',*,*,#2001,.F.);
#2003=DIRECTION('',(1.,0.,0.));
#2004=VECTOR('',#2003,1.);
#2005=CARTESIAN_POINT('',(0.6,-3.34465580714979,0.391578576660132));
#2006=LINE('',#2005,#2004);
#2007=EDGE_CURVE('E568',#873,#2000,#2006,.T.);
#2008=ORIENTED_EDGE('',*,*,#2007,.F.);
#2009=ORIENTED_EDGE('',*,*,#874,.F.);
#2010=ORIENTED_EDGE('',*,*,#222,.T.);
#2011=ORIENTED_EDGE('',*,*,#533,.T.);
#2012=ORIENTED_EDGE('',*,*,#1294,.F.);
#2013=EDGE_LOOP('',(#2002,#2008,#2009,#2010,#2011,#2012));
#2014=FACE_BOUND('',#2013,.T.);
#2015=ADVANCED_FACE('F1109',(#2014),#1994,.F.);
#2016=CARTESIAN_POINT('',(0.825,-2.77163859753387,1.14805029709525));
#2017=DIRECTION('',(0.,0.499999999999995,0.866025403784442));
#2018=DIRECTION('',(0.,-0.866025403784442,0.499999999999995));
#2019=AXIS2_PLACEMENT_3D('',#2016,#2017,#2018);
#2020=PLANE('',#2019);
#2021=ORIENTED_EDGE('',*,*,#520,.T.);
#2022=ORIENTED_EDGE('',*,*,#200,.T.);
#2023=ORIENTED_EDGE('',*,*,#889,.F.);
#2024=DIRECTION('',(1.,0.,0.));
#2025=VECTOR('',#2024,1.);
#2026=CARTESIAN_POINT('',(0.6,-3.09234618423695,1.33321090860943));
#2027=LINE('',#2026,#2025);
#2028=CARTESIAN_POINT('',(0.825,-3.09234618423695,1.33321090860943));
#2029=VERTEX_POINT('',#2028);
#2030=EDGE_CURVE('E546',#882,#2029,#2027,.T.);
#2031=ORIENTED_EDGE('',*,*,#2030,.T.);
#2032=DIRECTION('',(0.,-0.866025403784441,0.499999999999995));
#2033=VECTOR('',#2032,1.);
#2034=CARTESIAN_POINT('',(0.825,-2.77163859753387,1.14805029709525));
#2035=LINE('',#2034,#2033);
#2036=EDGE_CURVE('E720',#1278,#2029,#2035,.T.);
#2037=ORIENTED_EDGE('',*,*,#2036,.F.);
#2038=ORIENTED_EDGE('',*,*,#1279,.T.);
#2039=EDGE_LOOP('',(#2021,#2022,#2023,#2031,#2037,#2038));
#2040=FACE_BOUND('',#2039,.T.);
#2041=ADVANCED_FACE('F1107',(#2040),#2020,.F.);
#2042=CARTESIAN_POINT('',(0.825,0.,0.));
#2043=DIRECTION('',(1.,0.,0.));
#2044=DIRECTION('',(0.,0.,1.));
#2045=AXIS2_PLACEMENT_3D('',#2042,#2043,#2044);
#2046=PLANE('',#2045);
#2047=CARTESIAN_POINT('',(0.825,0.,0.));
#2048=DIRECTION('',(1.,0.,0.));
#2049=DIRECTION('',(0.,0.,-1.));
#2050=AXIS2_PLACEMENT_3D('',#2047,#2048,#2049);
#2051=CIRCLE('',#2050,3.3675);
#2052=EDGE_CURVE('E1308',#2000,#2029,#2051,.F.);
#2053=ORIENTED_EDGE('',*,*,#2052,.F.);
#2054=ORIENTED_EDGE('',*,*,#2001,.T.);
#2055=ORIENTED_EDGE('',*,*,#1288,.T.);
#2056=ORIENTED_EDGE('',*,*,#2036,.T.);
#2057=EDGE_LOOP('',(#2053,#2054,#2055,#2056));
#2058=FACE_BOUND('',#2057,.T.);
#2059=ADVANCED_FACE('F1098',(#2058),#2046,.T.);
#2060=CARTESIAN_POINT('',(0.825,-2.38006002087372,1.82628428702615));
#2061=DIRECTION('',(0.,-0.499999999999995,-0.866025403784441));
#2062=DIRECTION('',(0.,0.866025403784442,-0.499999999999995));
#2063=AXIS2_PLACEMENT_3D('',#2060,#2061,#2062);
#2064=PLANE('',#2063);
#2065=DIRECTION('',(0.,0.866025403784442,-0.499999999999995));
#2066=VECTOR('',#2065,1.);
#2067=CARTESIAN_POINT('',(0.825,-2.38006002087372,1.82628428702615));
#2068=LINE('',#2067,#2066);
#2069=CARTESIAN_POINT('',(0.825,-2.7007676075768,2.01144489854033));
#2070=VERTEX_POINT('',#2069);
#2071=EDGE_CURVE('E703',#2070,#1263,#2068,.T.);
#2072=ORIENTED_EDGE('',*,*,#2071,.F.);
#2073=DIRECTION('',(1.,0.,0.));
#2074=VECTOR('',#2073,1.);
#2075=CARTESIAN_POINT('',(0.6,-2.7007676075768,2.01144489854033));
#2076=LINE('',#2075,#2074);
#2077=EDGE_CURVE('E554',#897,#2070,#2076,.T.);
#2078=ORIENTED_EDGE('',*,*,#2077,.F.);
#2079=ORIENTED_EDGE('',*,*,#898,.F.);
#2080=ORIENTED_EDGE('',*,*,#185,.T.);
#2081=ORIENTED_EDGE('',*,*,#511,.T.);
#2082=ORIENTED_EDGE('',*,*,#1270,.F.);
#2083=EDGE_LOOP('',(#2072,#2078,#2079,#2080,#2081,#2082));
#2084=FACE_BOUND('',#2083,.T.);
#2085=ADVANCED_FACE('F1097',(#2084),#2064,.F.);
#2086=CARTESIAN_POINT('',(0.825,-1.82628428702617,2.3800600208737));
#2087=DIRECTION('',(0.,0.866025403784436,0.500000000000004));
#2088=DIRECTION('',(0.,-0.500000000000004,0.866025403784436));
#2089=AXIS2_PLACEMENT_3D('',#2086,#2087,#2088);
#2090=PLANE('',#2089);
#2091=ORIENTED_EDGE('',*,*,#498,.T.);
#2092=ORIENTED_EDGE('',*,*,#167,.T.);
#2093=ORIENTED_EDGE('',*,*,#913,.F.);
#2094=DIRECTION('',(1.,0.,0.));
#2095=VECTOR('',#2094,1.);
#2096=CARTESIAN_POINT('',(0.6,-2.01144489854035,2.70076760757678));
#2097=LINE('',#2096,#2095);
#2098=CARTESIAN_POINT('',(0.825,-2.01144489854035,2.70076760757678));
#2099=VERTEX_POINT('',#2098);
#2100=EDGE_CURVE('E536',#906,#2099,#2097,.T.);
#2101=ORIENTED_EDGE('',*,*,#2100,.T.);
#2102=DIRECTION('',(0.,-0.500000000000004,0.866025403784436));
#2103=VECTOR('',#2102,1.);
#2104=CARTESIAN_POINT('',(0.825,-1.82628428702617,2.3800600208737));
#2105=LINE('',#2104,#2103);
#2106=EDGE_CURVE('E699',#1254,#2099,#2105,.T.);
#2107=ORIENTED_EDGE('',*,*,#2106,.F.);
#2108=ORIENTED_EDGE('',*,*,#1255,.T.);
#2109=EDGE_LOOP('',(#2091,#2092,#2093,#2101,#2107,#2108));
#2110=FACE_BOUND('',#2109,.T.);
#2111=ADVANCED_FACE('F1096',(#2110),#2090,.F.);
#2112=CARTESIAN_POINT('',(0.825,0.,0.));
#2113=DIRECTION('',(1.,0.,0.));
#2114=DIRECTION('',(0.,0.499999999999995,0.866025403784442));
#2115=AXIS2_PLACEMENT_3D('',#2112,#2113,#2114);
#2116=PLANE('',#2115);
#2117=CARTESIAN_POINT('',(0.825,0.,0.));
#2118=DIRECTION('',(1.,0.,0.));
#2119=DIRECTION('',(0.,0.,-1.));
#2120=AXIS2_PLACEMENT_3D('',#2117,#2118,#2119);
#2121=CIRCLE('',#2120,3.3675);
#2122=EDGE_CURVE('E1309',#2070,#2099,#2121,.F.);
#2123=ORIENTED_EDGE('',*,*,#2122,.F.);
#2124=ORIENTED_EDGE('',*,*,#2071,.T.);
#2125=ORIENTED_EDGE('',*,*,#1264,.T.);
#2126=ORIENTED_EDGE('',*,*,#2106,.T.);
#2127=EDGE_LOOP('',(#2123,#2124,#2125,#2126));
#2128=FACE_BOUND('',#2127,.T.);
#2129=ADVANCED_FACE('F1073',(#2128),#2116,.T.);
#2130=CARTESIAN_POINT('',(0.825,-1.14805029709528,2.77163859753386));
#2131=DIRECTION('',(0.,-0.866025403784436,-0.500000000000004));
#2132=DIRECTION('',(0.,0.500000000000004,-0.866025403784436));
#2133=AXIS2_PLACEMENT_3D('',#2130,#2131,#2132);
#2134=PLANE('',#2133);
#2135=DIRECTION('',(0.,0.500000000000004,-0.866025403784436));
#2136=VECTOR('',#2135,1.);
#2137=CARTESIAN_POINT('',(0.825,-1.14805029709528,2.77163859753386));
#2138=LINE('',#2137,#2136);
#2139=CARTESIAN_POINT('',(0.825,-1.33321090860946,3.09234618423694));
#2140=VERTEX_POINT('',#2139);
#2141=EDGE_CURVE('E690',#2140,#1239,#2138,.T.);
#2142=ORIENTED_EDGE('',*,*,#2141,.F.);
#2143=DIRECTION('',(1.,0.,0.));
#2144=VECTOR('',#2143,1.);
#2145=CARTESIAN_POINT('',(0.6,-1.33321090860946,3.09234618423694));
#2146=LINE('',#2145,#2144);
#2147=EDGE_CURVE('E545',#921,#2140,#2146,.T.);
#2148=ORIENTED_EDGE('',*,*,#2147,.F.);
#2149=ORIENTED_EDGE('',*,*,#922,.F.);
#2150=ORIENTED_EDGE('',*,*,#152,.T.);
#2151=ORIENTED_EDGE('',*,*,#489,.T.);
#2152=ORIENTED_EDGE('',*,*,#1246,.F.);
#2153=EDGE_LOOP('',(#2142,#2148,#2149,#2150,#2151,#2152));
#2154=FACE_BOUND('',#2153,.T.);
#2155=ADVANCED_FACE('F1070',(#2154),#2134,.F.);
#2156=CARTESIAN_POINT('',(0.825,-0.391578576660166,2.97433458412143));
#2157=DIRECTION('',(0.,1.,0.));
#2158=DIRECTION('',(0.,0.,1.));
#2159=AXIS2_PLACEMENT_3D('',#2156,#2157,#2158);
#2160=PLANE('',#2159);
#2161=ORIENTED_EDGE('',*,*,#476,.T.);
#2162=ORIENTED_EDGE('',*,*,#134,.T.);
#2163=ORIENTED_EDGE('',*,*,#937,.F.);
#2164=DIRECTION('',(1.,0.,0.));
#2165=VECTOR('',#2164,1.);
#2166=CARTESIAN_POINT('',(0.6,-0.391578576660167,3.34465580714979));
#2167=LINE('',#2166,#2165);
#2168=CARTESIAN_POINT('',(0.825,-0.391578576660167,3.34465580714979));
#2169=VERTEX_POINT('',#2168);
#2170=EDGE_CURVE('E523',#930,#2169,#2167,.T.);
#2171=ORIENTED_EDGE('',*,*,#2170,.T.);
#2172=DIRECTION('',(0.,0.,1.));
#2173=VECTOR('',#2172,1.);
#2174=CARTESIAN_POINT('',(0.825,-0.391578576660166,2.97433458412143));
#2175=LINE('',#2174,#2173);
#2176=EDGE_CURVE('E681',#1230,#2169,#2175,.T.);
#2177=ORIENTED_EDGE('',*,*,#2176,.F.);
#2178=ORIENTED_EDGE('',*,*,#1231,.T.);
#2179=EDGE_LOOP('',(#2161,#2162,#2163,#2171,#2177,#2178));
#2180=FACE_BOUND('',#2179,.T.);
#2181=ADVANCED_FACE('F1064',(#2180),#2160,.F.);
#2182=CARTESIAN_POINT('',(0.825,0.,0.));
#2183=DIRECTION('',(1.,0.,0.));
#2184=DIRECTION('',(0.,0.866025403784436,0.500000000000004));
#2185=AXIS2_PLACEMENT_3D('',#2182,#2183,#2184);
#2186=PLANE('',#2185);
#2187=CARTESIAN_POINT('',(0.825,0.,0.));
#2188=DIRECTION('',(1.,0.,0.));
#2189=DIRECTION('',(0.,0.,-1.));
#2190=AXIS2_PLACEMENT_3D('',#2187,#2188,#2189);
#2191=CIRCLE('',#2190,3.3675);
#2192=EDGE_CURVE('E1307',#2140,#2169,#2191,.F.);
#2193=ORIENTED_EDGE('',*,*,#2192,.F.);
#2194=ORIENTED_EDGE('',*,*,#2141,.T.);
#2195=ORIENTED_EDGE('',*,*,#1240,.T.);
#2196=ORIENTED_EDGE('',*,*,#2176,.T.);
#2197=EDGE_LOOP('',(#2193,#2194,#2195,#2196));
#2198=FACE_BOUND('',#2197,.T.);
#2199=ADVANCED_FACE('F1062',(#2198),#2186,.T.);
#2200=CARTESIAN_POINT('',(0.825,0.391578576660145,2.97433458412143));
#2201=DIRECTION('',(0.,-1.,0.));
#2202=DIRECTION('',(0.,0.,-1.));
#2203=AXIS2_PLACEMENT_3D('',#2200,#2201,#2202);
#2204=PLANE('',#2203);
#2205=DIRECTION('',(0.,0.,-1.));
#2206=VECTOR('',#2205,1.);
#2207=CARTESIAN_POINT('',(0.825,0.391578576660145,2.97433458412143));
#2208=LINE('',#2207,#2206);
#2209=CARTESIAN_POINT('',(0.825,0.391578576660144,3.34465580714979));
#2210=VERTEX_POINT('',#2209);
#2211=EDGE_CURVE('E671',#2210,#1215,#2208,.T.);
#2212=ORIENTED_EDGE('',*,*,#2211,.F.);
#2213=DIRECTION('',(1.,0.,0.));
#2214=VECTOR('',#2213,1.);
#2215=CARTESIAN_POINT('',(0.6,0.391578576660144,3.34465580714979));
#2216=LINE('',#2215,#2214);
#2217=EDGE_CURVE('E526',#945,#2210,#2216,.T.);
#2218=ORIENTED_EDGE('',*,*,#2217,.F.);
#2219=ORIENTED_EDGE('',*,*,#946,.F.);
#2220=ORIENTED_EDGE('',*,*,#115,.T.);
#2221=ORIENTED_EDGE('',*,*,#467,.T.);
#2222=ORIENTED_EDGE('',*,*,#1222,.F.);
#2223=EDGE_LOOP('',(#2212,#2218,#2219,#2220,#2221,#2222));
#2224=FACE_BOUND('',#2223,.T.);
#2225=ADVANCED_FACE('F1022',(#2224),#2204,.F.);
#2226=CARTESIAN_POINT('',(0.825,1.14805029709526,2.77163859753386));
#2227=DIRECTION('',(0.,0.86602540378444,-0.499999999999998));
#2228=DIRECTION('',(0.,0.499999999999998,0.86602540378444));
#2229=AXIS2_PLACEMENT_3D('',#2226,#2227,#2228);
#2230=PLANE('',#2229);
#2231=ORIENTED_EDGE('',*,*,#449,.T.);
#2232=ORIENTED_EDGE('',*,*,#93,.T.);
#2233=ORIENTED_EDGE('',*,*,#961,.F.);
#2234=DIRECTION('',(1.,0.,0.));
#2235=VECTOR('',#2234,1.);
#2236=CARTESIAN_POINT('',(0.6,1.33321090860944,3.09234618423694));
#2237=LINE('',#2236,#2235);
#2238=CARTESIAN_POINT('',(0.825,1.33321090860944,3.09234618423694));
#2239=VERTEX_POINT('',#2238);
#2240=EDGE_CURVE('E503',#954,#2239,#2237,.T.);
#2241=ORIENTED_EDGE('',*,*,#2240,.T.);
#2242=DIRECTION('',(0.,0.499999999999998,0.86602540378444));
#2243=VECTOR('',#2242,1.);
#2244=CARTESIAN_POINT('',(0.825,1.14805029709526,2.77163859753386));
#2245=LINE('',#2244,#2243);
#2246=EDGE_CURVE('E667',#1206,#2239,#2245,.T.);
#2247=ORIENTED_EDGE('',*,*,#2246,.F.);
#2248=ORIENTED_EDGE('',*,*,#1207,.T.);
#2249=EDGE_LOOP('',(#2231,#2232,#2233,#2241,#2247,#2248));
#2250=FACE_BOUND('',#2249,.T.);
#2251=ADVANCED_FACE('F1032',(#2250),#2230,.F.);
#2252=CARTESIAN_POINT('',(0.825,0.,0.));
#2253=DIRECTION('',(1.,0.,0.));
#2254=DIRECTION('',(0.,1.,0.));
#2255=AXIS2_PLACEMENT_3D('',#2252,#2253,#2254);
#2256=PLANE('',#2255);
#2257=CARTESIAN_POINT('',(0.825,0.,0.));
#2258=DIRECTION('',(1.,0.,0.));
#2259=DIRECTION('',(0.,0.,-1.));
#2260=AXIS2_PLACEMENT_3D('',#2257,#2258,#2259);
#2261=CIRCLE('',#2260,3.3675);
#2262=EDGE_CURVE('E1303',#2210,#2239,#2261,.F.);
#2263=ORIENTED_EDGE('',*,*,#2262,.F.);
#2264=ORIENTED_EDGE('',*,*,#2211,.T.);
#2265=ORIENTED_EDGE('',*,*,#1216,.T.);
#2266=ORIENTED_EDGE('',*,*,#2246,.T.);
#2267=EDGE_LOOP('',(#2263,#2264,#2265,#2266));
#2268=FACE_BOUND('',#2267,.T.);
#2269=ADVANCED_FACE('F1060',(#2268),#2256,.T.);
#2270=CARTESIAN_POINT('',(0.825,1.82628428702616,2.38006002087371));
#2271=DIRECTION('',(0.,-0.86602540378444,0.499999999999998));
#2272=DIRECTION('',(0.,-0.499999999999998,-0.86602540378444));
#2273=AXIS2_PLACEMENT_3D('',#2270,#2271,#2272);
#2274=PLANE('',#2273);
#2275=DIRECTION('',(0.,-0.499999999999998,-0.86602540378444));
#2276=VECTOR('',#2275,1.);
#2277=CARTESIAN_POINT('',(0.825,1.82628428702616,2.38006002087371));
#2278=LINE('',#2277,#2276);
#2279=CARTESIAN_POINT('',(0.825,2.01144489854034,2.70076760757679));
#2280=VERTEX_POINT('',#2279);
#2281=EDGE_CURVE('E507',#2280,#1191,#2278,.T.);
#2282=ORIENTED_EDGE('',*,*,#2281,.F.);
#2283=DIRECTION('',(1.,0.,0.));
#2284=VECTOR('',#2283,1.);
#2285=CARTESIAN_POINT('',(0.6,2.01144489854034,2.70076760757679));
#2286=LINE('',#2285,#2284);
#2287=EDGE_CURVE('E506',#969,#2280,#2286,.T.);
#2288=ORIENTED_EDGE('',*,*,#2287,.F.);
#2289=ORIENTED_EDGE('',*,*,#970,.F.);
#2290=ORIENTED_EDGE('',*,*,#78,.T.);
#2291=ORIENTED_EDGE('',*,*,#440,.T.);
#2292=ORIENTED_EDGE('',*,*,#1198,.F.);
#2293=EDGE_LOOP('',(#2282,#2288,#2289,#2290,#2291,#2292));
#2294=FACE_BOUND('',#2293,.T.);
#2295=ADVANCED_FACE('F510',(#2294),#2274,.F.);
#2296=CARTESIAN_POINT('',(0.825,2.3800600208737,1.82628428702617));
#2297=DIRECTION('',(0.,0.500000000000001,-0.866025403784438));
#2298=DIRECTION('',(0.,0.866025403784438,0.500000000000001));
#2299=AXIS2_PLACEMENT_3D('',#2296,#2297,#2298);
#2300=PLANE('',#2299);
#2301=ORIENTED_EDGE('',*,*,#670,.T.);
#2302=ORIENTED_EDGE('',*,*,#44,.T.);
#2303=ORIENTED_EDGE('',*,*,#985,.F.);
#2304=DIRECTION('',(1.,0.,0.));
#2305=VECTOR('',#2304,1.);
#2306=CARTESIAN_POINT('',(0.6,2.70076760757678,2.01144489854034));
#2307=LINE('',#2306,#2305);
#2308=CARTESIAN_POINT('',(0.825,2.70076760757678,2.01144489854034));
#2309=VERTEX_POINT('',#2308);
#2310=EDGE_CURVE('E512',#978,#2309,#2307,.T.);
#2311=ORIENTED_EDGE('',*,*,#2310,.T.);
#2312=DIRECTION('',(0.,0.866025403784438,0.500000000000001));
#2313=VECTOR('',#2312,1.);
#2314=CARTESIAN_POINT('',(0.825,2.3800600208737,1.82628428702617));
#2315=LINE('',#2314,#2313);
#2316=EDGE_CURVE('E655',#1182,#2309,#2315,.T.);
#2317=ORIENTED_EDGE('',*,*,#2316,.F.);
#2318=ORIENTED_EDGE('',*,*,#1183,.T.);
#2319=EDGE_LOOP('',(#2301,#2302,#2303,#2311,#2317,#2318));
#2320=FACE_BOUND('',#2319,.T.);
#2321=ADVANCED_FACE('F1378',(#2320),#2300,.F.);
#2322=CARTESIAN_POINT('',(0.825,0.,0.));
#2323=DIRECTION('',(1.,0.,0.));
#2324=DIRECTION('',(0.,0.86602540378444,-0.499999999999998));
#2325=AXIS2_PLACEMENT_3D('',#2322,#2323,#2324);
#2326=PLANE('',#2325);
#2327=CARTESIAN_POINT('',(0.825,0.,0.));
#2328=DIRECTION('',(1.,0.,0.));
#2329=DIRECTION('',(0.,0.,-1.));
#2330=AXIS2_PLACEMENT_3D('',#2327,#2328,#2329);
#2331=CIRCLE('',#2330,3.3675);
#2332=EDGE_CURVE('E1296',#2280,#2309,#2331,.F.);
#2333=ORIENTED_EDGE('',*,*,#2332,.F.);
#2334=ORIENTED_EDGE('',*,*,#2281,.T.);
#2335=ORIENTED_EDGE('',*,*,#1192,.T.);
#2336=ORIENTED_EDGE('',*,*,#2316,.T.);
#2337=EDGE_LOOP('',(#2333,#2334,#2335,#2336));
#2338=FACE_BOUND('',#2337,.T.);
#2339=ADVANCED_FACE('F1381',(#2338),#2326,.T.);
#2340=CARTESIAN_POINT('',(0.6,0.,0.));
#2341=DIRECTION('',(1.,0.,0.));
#2342=DIRECTION('',(0.,0.,-1.));
#2343=AXIS2_PLACEMENT_3D('',#2340,#2341,#2342);
#2344=CYLINDRICAL_SURFACE('',#2343,3.3675);
#2345=ORIENTED_EDGE('',*,*,#1632,.T.);
#2346=ORIENTED_EDGE('',*,*,#1610,.F.);
#2347=ORIENTED_EDGE('',*,*,#1003,.F.);
#2348=ORIENTED_EDGE('',*,*,#1587,.T.);
#2349=EDGE_LOOP('',(#2345,#2346,#2347,#2348));
#2350=FACE_BOUND('',#2349,.T.);
#2351=ADVANCED_FACE('F1526',(#2350),#2344,.T.);
#2352=CARTESIAN_POINT('',(0.6,0.,0.));
#2353=DIRECTION('',(1.,0.,0.));
#2354=DIRECTION('',(0.,0.,-1.));
#2355=AXIS2_PLACEMENT_3D('',#2352,#2353,#2354);
#2356=CYLINDRICAL_SURFACE('',#2355,3.3675);
#2357=ORIENTED_EDGE('',*,*,#2332,.T.);
#2358=ORIENTED_EDGE('',*,*,#2310,.F.);
#2359=ORIENTED_EDGE('',*,*,#979,.F.);
#2360=ORIENTED_EDGE('',*,*,#2287,.T.);
#2361=EDGE_LOOP('',(#2357,#2358,#2359,#2360));
#2362=FACE_BOUND('',#2361,.T.);
#2363=ADVANCED_FACE('F511',(#2362),#2356,.T.);
#2364=CARTESIAN_POINT('',(0.6,0.,0.));
#2365=DIRECTION('',(1.,0.,0.));
#2366=DIRECTION('',(0.,0.,-1.));
#2367=AXIS2_PLACEMENT_3D('',#2364,#2365,#2366);
#2368=CYLINDRICAL_SURFACE('',#2367,3.3675);
#2369=ORIENTED_EDGE('',*,*,#2262,.T.);
#2370=ORIENTED_EDGE('',*,*,#2240,.F.);
#2371=ORIENTED_EDGE('',*,*,#955,.F.);
#2372=ORIENTED_EDGE('',*,*,#2217,.T.);
#2373=EDGE_LOOP('',(#2369,#2370,#2371,#2372));
#2374=FACE_BOUND('',#2373,.T.);
#2375=ADVANCED_FACE('F1027',(#2374),#2368,.T.);
#2376=CARTESIAN_POINT('',(0.6,0.,0.));
#2377=DIRECTION('',(1.,0.,0.));
#2378=DIRECTION('',(0.,0.,-1.));
#2379=AXIS2_PLACEMENT_3D('',#2376,#2377,#2378);
#2380=CYLINDRICAL_SURFACE('',#2379,3.3675);
#2381=ORIENTED_EDGE('',*,*,#2192,.T.);
#2382=ORIENTED_EDGE('',*,*,#2170,.F.);
#2383=ORIENTED_EDGE('',*,*,#931,.F.);
#2384=ORIENTED_EDGE('',*,*,#2147,.T.);
#2385=EDGE_LOOP('',(#2381,#2382,#2383,#2384));
#2386=FACE_BOUND('',#2385,.T.);
#2387=ADVANCED_FACE('F1498',(#2386),#2380,.T.);
#2388=CARTESIAN_POINT('',(0.6,0.,0.));
#2389=DIRECTION('',(1.,0.,0.));
#2390=DIRECTION('',(0.,0.,-1.));
#2391=AXIS2_PLACEMENT_3D('',#2388,#2389,#2390);
#2392=CYLINDRICAL_SURFACE('',#2391,3.3675);
#2393=ORIENTED_EDGE('',*,*,#2122,.T.);
#2394=ORIENTED_EDGE('',*,*,#2100,.F.);
#2395=ORIENTED_EDGE('',*,*,#907,.F.);
#2396=ORIENTED_EDGE('',*,*,#2077,.T.);
#2397=EDGE_LOOP('',(#2393,#2394,#2395,#2396));
#2398=FACE_BOUND('',#2397,.T.);
#2399=ADVANCED_FACE('F1502',(#2398),#2392,.T.);
#2400=CARTESIAN_POINT('',(0.6,0.,0.));
#2401=DIRECTION('',(1.,0.,0.));
#2402=DIRECTION('',(0.,0.,-1.));
#2403=AXIS2_PLACEMENT_3D('',#2400,#2401,#2402);
#2404=CYLINDRICAL_SURFACE('',#2403,3.3675);
#2405=ORIENTED_EDGE('',*,*,#2052,.T.);
#2406=ORIENTED_EDGE('',*,*,#2030,.F.);
#2407=ORIENTED_EDGE('',*,*,#883,.F.);
#2408=ORIENTED_EDGE('',*,*,#2007,.T.);
#2409=EDGE_LOOP('',(#2405,#2406,#2407,#2408));
#2410=FACE_BOUND('',#2409,.T.);
#2411=ADVANCED_FACE('F1510',(#2410),#2404,.T.);
#2412=CARTESIAN_POINT('',(0.6,0.,0.));
#2413=DIRECTION('',(1.,0.,0.));
#2414=DIRECTION('',(0.,0.,-1.));
#2415=AXIS2_PLACEMENT_3D('',#2412,#2413,#2414);
#2416=CYLINDRICAL_SURFACE('',#2415,3.3675);
#2417=ORIENTED_EDGE('',*,*,#1982,.T.);
#2418=ORIENTED_EDGE('',*,*,#1960,.F.);
#2419=ORIENTED_EDGE('',*,*,#859,.F.);
#2420=ORIENTED_EDGE('',*,*,#1937,.T.);
#2421=EDGE_LOOP('',(#2417,#2418,#2419,#2420));
#2422=FACE_BOUND('',#2421,.T.);
#2423=ADVANCED_FACE('F1513',(#2422),#2416,.T.);
#2424=CARTESIAN_POINT('',(0.6,0.,0.));
#2425=DIRECTION('',(1.,0.,0.));
#2426=DIRECTION('',(0.,0.,-1.));
#2427=AXIS2_PLACEMENT_3D('',#2424,#2425,#2426);
#2428=CYLINDRICAL_SURFACE('',#2427,3.3675);
#2429=ORIENTED_EDGE('',*,*,#1912,.T.);
#2430=ORIENTED_EDGE('',*,*,#1890,.F.);
#2431=ORIENTED_EDGE('',*,*,#835,.F.);
#2432=ORIENTED_EDGE('',*,*,#1867,.T.);
#2433=EDGE_LOOP('',(#2429,#2430,#2431,#2432));
#2434=FACE_BOUND('',#2433,.T.);
#2435=ADVANCED_FACE('F1520',(#2434),#2428,.T.);
#2436=CARTESIAN_POINT('',(0.6,0.,0.));
#2437=DIRECTION('',(1.,0.,0.));
#2438=DIRECTION('',(0.,0.,-1.));
#2439=AXIS2_PLACEMENT_3D('',#2436,#2437,#2438);
#2440=CYLINDRICAL_SURFACE('',#2439,3.3675);
#2441=ORIENTED_EDGE('',*,*,#1842,.T.);
#2442=ORIENTED_EDGE('',*,*,#1820,.F.);
#2443=ORIENTED_EDGE('',*,*,#811,.F.);
#2444=ORIENTED_EDGE('',*,*,#1797,.T.);
#2445=EDGE_LOOP('',(#2441,#2442,#2443,#2444));
#2446=FACE_BOUND('',#2445,.T.);
#2447=ADVANCED_FACE('F1439',(#2446),#2440,.T.);
#2448=CARTESIAN_POINT('',(0.6,0.,0.));
#2449=DIRECTION('',(1.,0.,0.));
#2450=DIRECTION('',(0.,0.,-1.));
#2451=AXIS2_PLACEMENT_3D('',#2448,#2449,#2450);
#2452=CYLINDRICAL_SURFACE('',#2451,3.3675);
#2453=ORIENTED_EDGE('',*,*,#1772,.T.);
#2454=ORIENTED_EDGE('',*,*,#1750,.F.);
#2455=ORIENTED_EDGE('',*,*,#787,.F.);
#2456=ORIENTED_EDGE('',*,*,#1727,.T.);
#2457=EDGE_LOOP('',(#2453,#2454,#2455,#2456));
#2458=FACE_BOUND('',#2457,.T.);
#2459=ADVANCED_FACE('F1318',(#2458),#2452,.T.);
#2460=CARTESIAN_POINT('',(0.6,0.,0.));
#2461=DIRECTION('',(1.,0.,0.));
#2462=DIRECTION('',(0.,0.,-1.));
#2463=AXIS2_PLACEMENT_3D('',#2460,#2461,#2462);
#2464=CYLINDRICAL_SURFACE('',#2463,3.3675);
#2465=ORIENTED_EDGE('',*,*,#1702,.T.);
#2466=ORIENTED_EDGE('',*,*,#1680,.F.);
#2467=ORIENTED_EDGE('',*,*,#1056,.F.);
#2468=ORIENTED_EDGE('',*,*,#1657,.T.);
#2469=EDGE_LOOP('',(#2465,#2466,#2467,#2468));
#2470=FACE_BOUND('',#2469,.T.);
#2471=ADVANCED_FACE('F1523',(#2470),#2464,.T.);
#2472=CLOSED_SHELL('',(#66,#99,#140,#173,#206,#247,#280,#313,#354,#387,#428,#460,#482,#504,#526,
#548,#570,#592,#614,#636,#663,#685,#702,#722,#742,#762,#1066,#1089,#1111,#1418,#1438,#1458,
#1478,#1487,#1513,#1539,#1557,#1569,#1595,#1621,#1639,#1665,#1691,#1709,#1735,#1761,#1779,#1805,
#1831,#1849,#1875,#1901,#1919,#1945,#1971,#1989,#2015,#2041,#2059,#2085,#2111,#2129,#2155,#2181,
#2199,#2225,#2251,#2269,#2295,#2321,#2339,#2351,#2363,#2375,#2387,#2399,#2411,#2423,#2435,#2447,
#2459,#2471));
#2473=MANIFOLD_SOLID_BREP('B2',#2472);
#2474=ADVANCED_BREP_SHAPE_REPRESENTATION('',(#18,#2473),#14);
#2475=SHAPE_DEFINITION_REPRESENTATION(#9,#2474);
ENDSEC;
END-ISO-10303-21;
